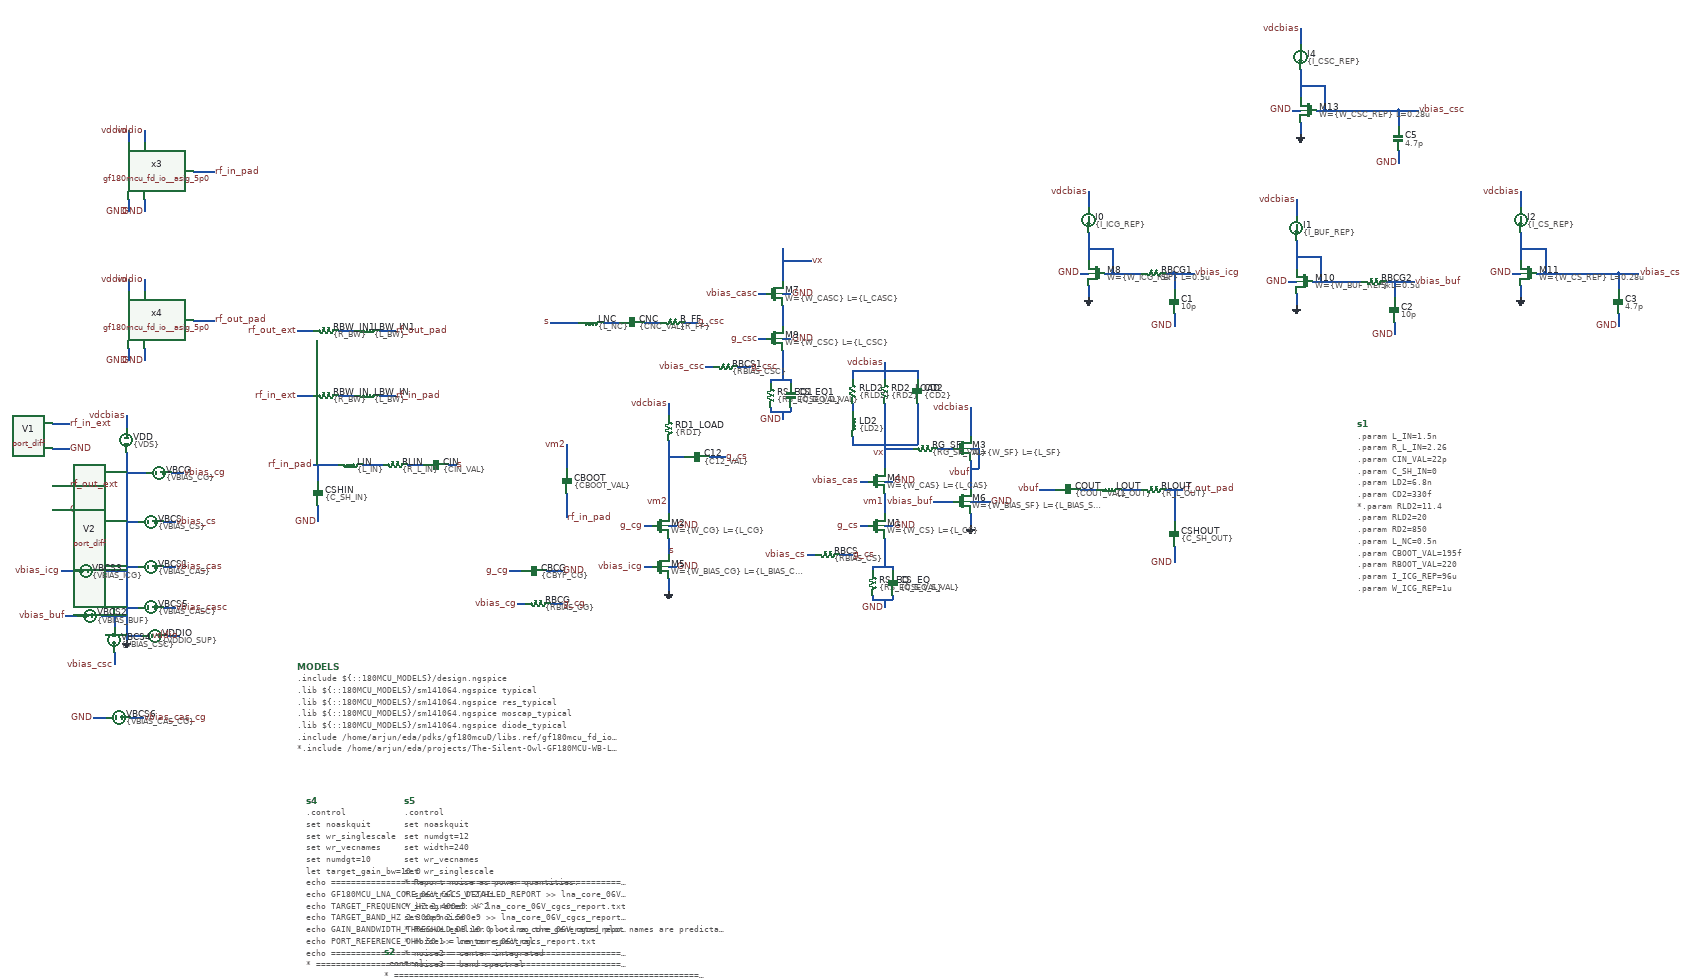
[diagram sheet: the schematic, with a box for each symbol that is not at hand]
v {xschem version=3.4.8RC file_version=1.3}
G {}
K {}
V {}
S {}
F {}
E {}
N -320 -440 -320 -410 {
lab=GND}
N 1010 -260 1030 -260 {
lab=GND}
N -320 -410 -320 -310 {
lab=GND}
N -320 -530 -320 -500 {
lab=vdcbias}
N -320 -390 -270 -390 {
lab=GND}
N -500 -510 -460 -510 {
lab=rf_in_ext}
N -500 -450 -460 -450 {
lab=GND}
N -500 -360 -460 -360 {
lab=rf_out_ext}
N -500 -300 -460 -300 {
lab=GND}
N 1010 -470 1010 -390 {
lab=vm2}
N 1010 -560 1010 -530 {
lab=vdcbias}
N -210 -390 -180 -390 {
lab=vbias_cg}
N 470 -410 490 -410 {
lab=s}
N 140 -410 170 -410 {
lab=rf_in_pad}
N 1010 -430 1050 -430 {
lab=vm2}
N 1110 -430 1150 -430 {
lab=g_cs}
N 1010 -230 1010 -220 {
lab=s}
N 1010 -220 1010 -190 {
lab=s}
N 950 -260 970 -260 {
lab=g_cg}
N -320 -310 -320 -110 {
lab=GND}
N 640 -70 660 -70 {
lab=vbias_cg}
N 720 -70 750 -70 {
lab=g_cg}
N 620 -150 650 -150 {
lab=g_cg}
N 710 -150 750 -150 {
lab=GND}
N 300 -580 340 -580 {
lab=rf_in_pad}
N 200 -580 240 -580 {
lab=#net1}
N 100 -580 140 -580 {
lab=rf_in_ext}
N -320 -270 -290 -270 {
lab=GND}
N -220 10 -190 10 {
lab=vddio}
N 300 -740 340 -740 {
lab=rf_out_pad}
N 200 -740 240 -740 {
lab=#net2}
N 100 -740 140 -740 {
lab=rf_out_ext}
N -320 10 -280 10 {
lab=GND}
N -230 -270 -200 -270 {
lab=vbias_cs
spice_ignore=true}
N 1540 -260 1560 -260 {
lab=GND}
N 1540 -230 1540 -220 {
lab=#net3}
N 1480 -260 1500 -260 {
lab=g_cs}
N 1350 -190 1370 -190 {
lab=vbias_cs}
N 1430 -190 1460 -190 {
lab=g_cs}
N 1540 -220 1540 -160 {
lab=#net3}
N 1540 -660 1540 -620 {
lab=vdcbias}
N 1750 -550 1750 -480 {
lab=vdcbias}
N 1750 -420 1750 -350 {
lab=vbuf}
N 1750 -290 1750 -260 {
lab=GND}
N 1750 -450 1770 -450 {
lab=vbuf}
N 1920 -350 1960 -350 {
lab=vbuf}
N 2020 -350 2060 -350 {
lab=#net4}
N 2120 -350 2170 -350 {
lab=#net5}
N 2230 -350 2270 -350 {
lab=rf_out_pad}
N 2250 -350 2250 -270 {
lab=rf_out_pad}
N 2250 -210 2250 -170 {
lab=GND}
N 150 -410 150 -370 {
lab=rf_in_pad}
N 150 -310 150 -270 {
lab=GND}
N 170 -410 200 -410 {
lab=rf_in_pad}
N 260 -410 310 -410 {
lab=#net6}
N 370 -410 410 -410 {
lab=#net7}
N 1540 -370 1560 -370 {
lab=GND}
N 1540 -340 1540 -330 {
lab=vm1}
N 1480 -370 1500 -370 {
lab=vbias_cas}
N 1540 -560 1540 -480 {
lab=vx}
N 1540 -330 1540 -290 {
lab=vm1}
N -320 -110 -320 20 {
lab=GND}
N -230 -160 -200 -160 {
lab=vbias_cas}
N -320 -160 -290 -160 {
lab=GND}
N 1770 -450 1770 -400 {
lab=vbuf}
N 1750 -400 1770 -400 {
lab=vbuf}
N 1010 -160 1030 -160 {
lab=GND}
N 1010 -130 1010 -120 {
lab=GND}
N 950 -160 970 -160 {
lab=vbias_icg}
N 1010 -120 1010 -100 {
lab=GND}
N 1660 -320 1710 -320 {
lab=vbias_buf}
N 1750 -320 1800 -320 {
lab=GND}
N -470 -40 -440 -40 {
lab=vbias_buf
spice_ignore=true}
N -380 -40 -320 -40 {
lab=GND}
N -480 -150 -450 -150 {
lab=vbias_icg
spice_ignore=true}
N -390 -150 -320 -150 {
lab=GND}
N 1560 -160 1560 -150 {
lab=#net3}
N 1510 -160 1560 -160 {
lab=#net3}
N 1560 -90 1560 -80 {
lab=GND}
N 1510 -80 1560 -80 {
lab=GND}
N 1510 -160 1510 -150 {
lab=#net3}
N 1510 -90 1510 -80 {
lab=GND}
N 1540 -80 1540 -60 {
lab=GND}
N 1670 -450 1710 -450 {
lab=#net8}
N 1540 -450 1610 -450 {
lab=vx}
N -155 -1130 -105 -1130 {
lab=rf_in_pad
}
N -315 -1060 -315 -1030 {
lab=GND
}
N -275 -1060 -275 -1030 {
lab=GND
}
N -315 -1230 -315 -1200 {
lab=vddio
}
N -275 -1230 -275 -1200 {
lab=vddio
}
N -155 -765 -105 -765 {
lab=rf_out_pad
}
N -315 -695 -315 -665 {
lab=GND
}
N -275 -695 -275 -665 {
lab=GND
}
N -315 -865 -315 -835 {
lab=vddio
}
N -275 -865 -275 -835 {
lab=vddio
}
N 1290 -720 1310 -720 {
lab=GND}
N 1290 -690 1290 -680 {
lab=#net9}
N 1230 -720 1250 -720 {
lab=g_csc}
N 1100 -650 1120 -650 {
lab=vbias_csc}
N 1180 -650 1210 -650 {
lab=g_csc}
N 1290 -680 1290 -620 {
lab=#net9}
N 1290 -830 1310 -830 {
lab=GND}
N 1290 -800 1290 -790 {
lab=#net10}
N 1230 -830 1250 -830 {
lab=vbias_casc}
N 1290 -940 1290 -860 {
lab=vx}
N 1290 -790 1290 -750 {
lab=#net10}
N 1310 -620 1310 -610 {
lab=#net9}
N 1260 -620 1310 -620 {
lab=#net9}
N 1310 -550 1310 -540 {
lab=GND}
N 1260 -540 1310 -540 {
lab=GND}
N 1260 -620 1260 -610 {
lab=#net9}
N 1260 -550 1260 -540 {
lab=GND}
N 1290 -540 1290 -520 {
lab=GND}
N 1290 -910 1360 -910 {
lab=vx}
N -230 -270 -200 -270 {lab=vbias_cs
spice_ignore=true}
N -350 -40 -350 -10 {
lab=GND}
N -350 50 -350 80 {
lab=vbias_csc
spice_ignore=true}
N -230 -60 -200 -60 {
lab=vbias_casc}
N -320 -60 -290 -60 {
lab=GND}
N 850 -760 890 -760 {
lab=s}
N 950 -760 990 -760 {
lab=#net11}
N 1010 -330 1010 -320 {
lab=vm2}
N 1010 -320 1010 -290 {lab=vm2}
N -308.75 210 -278.75 210 {
lab=vbias_cas_cg
spice_ignore=true}
N -400 210 -368.75 210 {
lab=GND
spice_ignore=true}
N 1460 -640 1460 -620 {lab=vdcbias}
N 1460 -640 1540 -640 {lab=vdcbias}
N 1460 -560 1460 -540 {lab=#net12}
N 1620 -560 1620 -550 {lab=vx}
N 1540 -460 1620 -460 {lab=vx}
N 1620 -640 1620 -620 {lab=vdcbias}
N 1540 -640 1620 -640 {lab=vdcbias}
N 1620 -550 1620 -540 {lab=vx}
N 1010 -390 1010 -330 {lab=vm2}
N 1540 -480 1540 -400 {lab=vx}
N 1460 -480 1460 -460 {lab=vx}
N 1460 -460 1540 -460 {lab=vx}
N 1620 -540 1620 -460 {lab=vx}
N 720 -760 790 -760 {lab=s}
N 1050 -760 1080 -760 {lab=g_csc}
N 760 -460 760 -400 {lab=vm2}
N 760 -340 760 -280 {lab=rf_in_pad}
N 2020 -880 2040 -880 {
lab=GND}
N 2040 -850 2040 -840 {
lab=GND}
N 2080 -880 2100 -880 {
lab=#net13}
N 2040 -840 2040 -820 {
lab=GND}
N 2040 -980 2040 -910 {lab=#net13}
N 2100 -880 2170 -880 {lab=#net13}
N 2040 -940 2100 -940 {lab=#net13}
N 2100 -940 2100 -880 {lab=#net13}
N 2040 -1080 2040 -1040 {lab=vdcbias}
N 2530 -860 2550 -860 {
lab=GND
}
N 2550 -830 2550 -820 {
lab=GND
}
N 2590 -860 2610 -860 {
lab=#net14
}
N 2550 -820 2550 -800 {
lab=GND
}
N 2550 -960 2550 -890 {lab=#net14
}
N 2550 -920 2610 -920 {lab=#net14
}
N 2610 -920 2610 -860 {lab=#net14
}
N 2550 -1060 2550 -1020 {lab=vdcbias
}
N 2230 -880 2250 -880 {lab=vbias_icg}
N 2250 -880 2250 -840 {lab=vbias_icg}
N 2250 -880 2300 -880 {lab=vbias_icg}
N 2250 -780 2250 -750 {lab=GND}
N 2640 -860 2710 -860 {lab=#net14}
N 2770 -860 2790 -860 {lab=vbias_buf}
N 2790 -860 2790 -820 {lab=vbias_buf}
N 2790 -760 2790 -730 {lab=GND}
N 2610 -860 2640 -860 {lab=#net14}
N 2790 -860 2840 -860 {lab=vbias_buf}
N 3080 -880 3100 -880 {
lab=GND
}
N 3100 -850 3100 -840 {
lab=GND
}
N 3140 -880 3160 -880 {
lab=vbias_cs
}
N 3100 -840 3100 -820 {
lab=GND
}
N 3100 -980 3100 -910 {lab=vbias_cs
}
N 3100 -940 3160 -940 {lab=vbias_cs
}
N 3160 -940 3160 -880 {lab=vbias_cs
}
N 3100 -1080 3100 -1040 {lab=vdcbias
}
N 3190 -880 3260 -880 {lab=vbias_cs}
N 3320 -880 3340 -880 {lab=vbias_cs}
N 3340 -880 3340 -840 {lab=vbias_cs}
N 3340 -780 3340 -750 {lab=GND}
N 3160 -880 3190 -880 {lab=vbias_cs}
N 3340 -880 3390 -880 {lab=vbias_cs}
N 3260 -880 3320 -880 {lab=vbias_cs}
N 2540 -1280 2560 -1280 {
lab=GND
}
N 2560 -1250 2560 -1240 {
lab=GND
}
N 2600 -1280 2620 -1280 {
lab=vbias_csc
}
N 2560 -1240 2560 -1220 {
lab=GND
}
N 2560 -1380 2560 -1310 {lab=vbias_csc
}
N 2560 -1340 2620 -1340 {lab=vbias_csc
}
N 2620 -1340 2620 -1280 {lab=vbias_csc
}
N 2560 -1480 2560 -1440 {lab=vdcbias
}
N 2650 -1280 2720 -1280 {lab=vbias_csc}
N 2780 -1280 2800 -1280 {lab=vbias_csc}
N 2800 -1280 2800 -1240 {lab=vbias_csc}
N 2800 -1180 2800 -1150 {lab=GND}
N 2620 -1280 2650 -1280 {lab=vbias_csc}
N 2800 -1280 2850 -1280 {lab=vbias_csc}
N 2720 -1280 2780 -1280 {lab=vbias_csc}
C {vsource.sym} -240 -390 1 0 {name=VBCG value=\{VBIAS_CG\} savecurrent=false}
C {gnd.sym} 1010 -100 0 0 {name=l1 lab=GND}
C {vsource.sym} -320 -470 0 0 {name=VDD value=\{VDS\} savecurrent=false}
C {capa.sym} 1080 -430 3 0 {name=C12
m=1
value=\{C12_VAL\}
footprint=1206
device="ceramic capacitor"}
C {lab_pin.sym} -460 -510 2 0 {name=p5 sig_type=std_logic lab=rf_in_ext}
C {lab_pin.sym} -460 -450 2 0 {name=p6 sig_type=std_logic lab=GND

}
C {lab_pin.sym} -460 -300 2 0 {name=p8 sig_type=std_logic lab=GND}
C {capa.sym} 440 -410 3 0 {name=CIN
m=1
value=\{CIN_VAL\}
footprint=1206
device="ceramic capacitor"}
C {gnd.sym} -320 20 0 0 {name=l3 lab=GND}
C {lab_pin.sym} -320 -530 0 0 {name=p10 sig_type=std_logic lab=vdcbias
}
C {lab_pin.sym} -180 -390 2 0 {name=p9 sig_type=std_logic lab=vbias_cg}
C {lab_pin.sym} 1010 -560 0 0 {name=p11 sig_type=std_logic lab=vdcbias
}
C {lab_pin.sym} 1150 -430 2 0 {name=p14 sig_type=std_logic lab=g_cs}
C {port_diff.sym} -500 -480 0 0 {name=V1 portnum=1 Z0=50 DCval=0 ACmag=1 ACphase=0 TRANval=""}
C {port_diff.sym} -500 -330 0 0 {name=V2 portnum=2 Z0=50 DCval=0 ACmag=1 ACphase=0 TRANval=""}
C {lab_pin.sym} 1010 -200 2 0 {name=p1 sig_type=std_logic lab=s}
C {lab_pin.sym} 1030 -260 2 0 {name=p2 sig_type=std_logic lab=GND}
C {symbols/nfet_06v0.sym} 990 -260 0 0 {name=M2
L=\{L_CG\}
W=\{W_CG\}
nf=10
m=\{M_CG\}
ad="'int((nf+1)/2) * W/nf * 0.18u'"
pd="'2*int((nf+1)/2) * (W/nf + 0.18u)'"
as="'int((nf+2)/2) * W/nf * 0.18u'"
ps="'2*int((nf+2)/2) * (W/nf + 0.18u)'"
nrd="'0.18u / W'" nrs="'0.18u / W'"
sa=0 sb=0 sd=0
model=nfet_06v0
spiceprefix=X
}
C {lab_pin.sym} 490 -410 2 0 {name=p17 sig_type=std_logic lab=s}
C {res.sym} 690 -70 1 0 {name=RBCG
value=\{RBIAS_CG\}
footprint=1206
device=resistor
m=1}
C {lab_pin.sym} 640 -70 0 0 {name=p20 sig_type=std_logic lab=vbias_cg}
C {lab_pin.sym} 750 -70 2 0 {name=p21 sig_type=std_logic lab=g_cg}
C {capa.sym} 680 -150 3 0 {name=CBCG
m=1
value=\{CBYP_CG\}
footprint=1206
device="ceramic capacitor"}
C {lab_pin.sym} 750 -150 2 0 {name=p19 sig_type=std_logic lab=GND}
C {ind.sym} 270 -580 1 0 {name=LBW_IN
m=1
value=\{L_BW\}
footprint=1206
device=inductor
}
C {res.sym} 170 -580 1 0 {name=RBW_IN
value=\{R_BW\}
footprint=1206
device=resistor
m=1
}
C {lab_pin.sym} 100 -580 0 0 {name=p22 sig_type=std_logic lab=rf_in_ext}
C {lab_pin.sym} 340 -580 2 0 {name=p25 sig_type=std_logic lab=rf_in_pad}
C {vsource.sym} -250 10 1 0 {name=VDDIO value=\{VDDIO_SUP\} savecurrent=false}
C {lab_pin.sym} -190 10 1 0 {name=p27 sig_type=std_logic lab=vddio
}
C {lab_pin.sym} 140 -410 0 0 {name=p13 sig_type=std_logic lab=rf_in_pad}
C {ind.sym} 270 -740 1 0 {name=LBW_IN1
m=1
value=\{L_BW\}
footprint=1206
device=inductor}
C {res.sym} 170 -740 1 0 {name=RBW_IN1
value=\{R_BW\}
footprint=1206
device=resistor
m=1}
C {lab_pin.sym} 100 -740 0 0 {name=p37 sig_type=std_logic lab=rf_out_ext}
C {lab_pin.sym} 340 -740 2 0 {name=p38 sig_type=std_logic lab=rf_out_pad}
C {lab_pin.sym} -460 -360 2 0 {name=p7 sig_type=std_logic lab=rf_out_ext}
C {vsource.sym} -260 -270 1 0 {name=VBCS value=\{VBIAS_CS\} savecurrent=false
spice_ignore=true}
C {lab_pin.sym} -200 -270 2 0 {name=p12 sig_type=std_logic lab=vbias_cs
spice_ignore=true}
C {lab_pin.sym} 950 -260 0 0 {name=p4 sig_type=std_logic lab=g_cg}
C {lab_pin.sym} 620 -150 0 0 {name=p15 sig_type=std_logic lab=g_cg}
C {res.sym} 1010 -500 0 0 {name=RD1_LOAD
value=\{RD1\}
footprint=1206
device=resistor
m=1
}
C {lab_pin.sym} 1540 -60 3 0 {name=p16 sig_type=std_logic lab=GND}
C {lab_pin.sym} 1480 -260 0 0 {name=p18 sig_type=std_logic lab=g_cs}
C {res.sym} 1400 -190 1 0 {name=RBCS
value=\{RBIAS_CS\}
footprint=1206
device=resistor
m=1}
C {lab_pin.sym} 1350 -190 0 0 {name=p23 sig_type=std_logic lab=vbias_cs}
C {lab_pin.sym} 1460 -190 2 0 {name=p24 sig_type=std_logic lab=g_cs}
C {res.sym} 1540 -590 0 0 {name=RD2_LOAD
value=\{RD2\}
footprint=1206
device=resistor
m=1
}
C {lab_pin.sym} 1540 -660 0 0 {name=p39 sig_type=std_logic lab=vdcbias
}
C {symbols/nfet_06v0.sym} 1730 -450 0 0 {name=M3
L=\{L_SF\}
W=\{W_SF\}
nf=10
m=\{M_SF\}
ad="'int((nf+1)/2) * W/nf * 0.18u'"
pd="'2*int((nf+1)/2) * (W/nf + 0.18u)'"
as="'int((nf+2)/2) * W/nf * 0.18u'"
ps="'2*int((nf+2)/2) * (W/nf + 0.18u)'"
nrd="'0.18u / W'" nrs="'0.18u / W'"
sa=0 sb=0 sd=0
model=nfet_06v0
spiceprefix=X
}
C {lab_pin.sym} 1750 -550 0 0 {name=p40 sig_type=std_logic lab=vdcbias
}
C {gnd.sym} 1750 -260 0 0 {name=l2 lab=GND}
C {capa.sym} 1990 -350 3 0 {name=COUT
m=1
value=\{COUT_VAL\}
footprint=1206
device="ceramic capacitor"}
C {lab_pin.sym} 1750 -390 0 0 {name=p43 sig_type=std_logic lab=vbuf}
C {lab_pin.sym} 1920 -350 0 0 {name=p44 sig_type=std_logic lab=vbuf}
C {lab_pin.sym} 2270 -350 2 0 {name=p45 sig_type=std_logic lab=rf_out_pad}
C {ind.sym} 2090 -350 1 0 {name=LOUT
m=1
value=\{L_OUT\}
footprint=1206
device=inductor
}
C {res.sym} 2200 -350 1 0 {name=RLOUT
value=\{R_L_OUT\}
footprint=1206
device=resistor
m=1}
C {capa.sym} 2250 -240 0 0 {name=CSHOUT
m=1
value=\{C_SH_OUT\}
footprint=1206
device="ceramic capacitor"}
C {lab_pin.sym} 2250 -170 3 0 {name=p42 sig_type=std_logic lab=GND}
C {capa.sym} 150 -340 0 0 {name=CSHIN
m=1
value=\{C_SH_IN\}
footprint=1206
device="ceramic capacitor"}
C {lab_pin.sym} 150 -270 3 0 {name=p46 sig_type=std_logic lab=GND}
C {ind.sym} 230 -410 1 0 {name=LIN
m=1
value=\{L_IN\}
footprint=1206
device=inductor
}
C {res.sym} 340 -410 1 0 {name=RLIN
value=\{R_L_IN\}
footprint=1206
device=resistor
m=1
}
C {symbols/nfet_06v0.sym} 1520 -370 0 0 {name=M4
L=\{L_CAS\}
W=\{W_CAS\}
nf=10
m=\{M_CAS\}
ad="'int((nf+1)/2) * W/nf * 0.18u'"
pd="'2*int((nf+1)/2) * (W/nf + 0.18u)'"
as="'int((nf+2)/2) * W/nf * 0.18u'"
ps="'2*int((nf+2)/2) * (W/nf + 0.18u)'"
nrd="'0.18u / W'" nrs="'0.18u / W'"
sa=0 sb=0 sd=0
model=nfet_06v0
spiceprefix=X
}
C {lab_pin.sym} 1480 -370 0 0 {name=p47 sig_type=std_logic lab=vbias_cas}
C {lab_pin.sym} 1560 -370 2 0 {name=p48 sig_type=std_logic lab=GND}
C {vsource.sym} -260 -160 1 0 {name=VBCS1 value=\{VBIAS_CAS\} savecurrent=false}
C {lab_pin.sym} -200 -160 2 0 {name=p49 sig_type=std_logic lab=vbias_cas}
C {lab_pin.sym} 1030 -160 2 0 {name=p41 sig_type=std_logic lab=GND}
C {lab_pin.sym} 950 -160 0 0 {name=p50 sig_type=std_logic lab=vbias_icg}
C {lab_pin.sym} 1660 -320 0 0 {name=p51 sig_type=std_logic lab=vbias_buf}
C {lab_pin.sym} 1800 -320 2 0 {name=p52 sig_type=std_logic lab=GND}
C {vsource.sym} -410 -40 3 0 {name=VBCS2 value=\{VBIAS_BUF\} savecurrent=false
spice_ignore=true}
C {lab_pin.sym} -470 -40 0 0 {name=p53 sig_type=std_logic lab=vbias_buf
spice_ignore=true}
C {vsource.sym} -420 -150 3 0 {name=VBCS3 value=\{VBIAS_ICG\} savecurrent=false
spice_ignore=true}
C {lab_pin.sym} -480 -150 0 0 {name=p54 sig_type=std_logic lab=vbias_icg
spice_ignore=true}
C {symbols/nfet_03v3.sym} 990 -160 0 0 {name=M5
L=\{L_BIAS_CG\}
W=\{W_BIAS_CG\}
nf=10
m=\{M_BIAS_CG\}
ad="'int((nf+1)/2) * W/nf * 0.18u'"
pd="'2*int((nf+1)/2) * (W/nf + 0.18u)'"
as="'int((nf+2)/2) * W/nf * 0.18u'"
ps="'2*int((nf+2)/2) * (W/nf + 0.18u)'"
nrd="'0.18u / W'" nrs="'0.18u / W'"
sa=0 sb=0 sd=0
model=nfet_03v3
spiceprefix=X
}
C {symbols/nfet_03v3.sym} 1730 -320 0 0 {name=M6
L=\{L_BIAS_SF\}
W=\{W_BIAS_SF\}
nf=10
m=\{M_BIAS_SF\}
ad="'int((nf+1)/2) * W/nf * 0.18u'"
pd="'2*int((nf+1)/2) * (W/nf + 0.18u)'"
as="'int((nf+2)/2) * W/nf * 0.18u'"
ps="'2*int((nf+2)/2) * (W/nf + 0.18u)'"
nrd="'0.18u / W'" nrs="'0.18u / W'"
sa=0 sb=0 sd=0
model=nfet_03v3
spiceprefix=X
}
C {res.sym} 1510 -120 0 0 {name=RS_EQ
value=\{RS_EQ_S_VAL\}
footprint=1206
device=resistor
m=1
}
C {capa.sym} 1560 -120 0 0 {name=CS_EQ
m=1
value=\{CSEQ_S_VAL\}
footprint=1206
device="ceramic capacitor"}
C {lab_pin.sym} 1560 -260 2 0 {name=p55 sig_type=std_logic lab=GND}
C {symbols/nfet_03v3.sym} 1520 -260 0 0 {name=M1
L=\{L_CS\}
W=\{W_CS\}
nf=10
m=\{M_CS\}
ad="'int((nf+1)/2) * W/nf * 0.18u'"
pd="'2*int((nf+1)/2) * (W/nf + 0.18u)'"
as="'int((nf+2)/2) * W/nf * 0.18u'"
ps="'2*int((nf+2)/2) * (W/nf + 0.18u)'"
nrd="'0.18u / W'" nrs="'0.18u / W'"
sa=0 sb=0 sd=0
model=nfet_03v3
spiceprefix=X
}
C {res.sym} 1640 -450 1 0 {name=RG_SF
value=\{RG_SF_VAL\}
footprint=1206
device=resistor
m=1}
C {lab_pin.sym} -105 -1130 2 0 {name=p56 sig_type=std_logic lab=rf_in_pad
}
C {lab_pin.sym} -315 -1230 1 0 {name=p57 sig_type=std_logic lab=vddio
}
C {lab_pin.sym} -275 -1230 1 0 {name=p58 sig_type=std_logic lab=vddio
}
C {lab_pin.sym} -315 -1030 3 0 {name=p59 sig_type=std_logic lab=GND
}
C {lab_pin.sym} -275 -1030 3 0 {name=p60 sig_type=std_logic lab=GND
}
C {/home/arjun/eda/projects/The-Silent-Owl-GF180MCU-WB-LNA/analog_pad_sp_paramerters/xschem/gf180mcu_fd_io__asig_5p0.sym} -305 -1130 0 0 {name=x3 model=gf180mcu_fd_io__asig_5p0
}
C {lab_pin.sym} -315 -865 1 0 {name=p61 sig_type=std_logic lab=vddio
}
C {lab_pin.sym} -275 -865 1 0 {name=p62 sig_type=std_logic lab=vddio
}
C {lab_pin.sym} -315 -665 3 0 {name=p63 sig_type=std_logic lab=GND
}
C {lab_pin.sym} -275 -665 3 0 {name=p64 sig_type=std_logic lab=GND
}
C {lab_pin.sym} -105 -765 2 0 {name=p65 sig_type=std_logic lab=rf_out_pad
}
C {/home/arjun/eda/projects/The-Silent-Owl-GF180MCU-WB-LNA/analog_pad_sp_paramerters/xschem/gf180mcu_fd_io__asig_5p0.sym} -305 -765 0 0 {name=x4 model=gf180mcu_fd_io__asig_5p0
}
C {lab_pin.sym} 1290 -520 3 0 {name=p26 sig_type=std_logic lab=GND}
C {lab_pin.sym} 1230 -720 0 0 {name=p28 sig_type=std_logic lab=g_csc}
C {res.sym} 1150 -650 1 0 {name=RBCS1
value=\{RBIAS_CSC\}
footprint=1206
device=resistor
m=1}
C {lab_pin.sym} 1100 -650 0 0 {name=p29 sig_type=std_logic lab=vbias_csc}
C {lab_pin.sym} 1210 -650 2 0 {name=p30 sig_type=std_logic lab=g_csc}
C {symbols/nfet_06v0.sym} 1270 -830 0 0 {name=M7
L=\{L_CASC\}
W=\{W_CASC\}
nf=10
m=\{M_CASC\}
ad="'int((nf+1)/2) * W/nf * 0.18u'"
pd="'2*int((nf+1)/2) * (W/nf + 0.18u)'"
as="'int((nf+2)/2) * W/nf * 0.18u'"
ps="'2*int((nf+2)/2) * (W/nf + 0.18u)'"
nrd="'0.18u / W'" nrs="'0.18u / W'"
sa=0 sb=0 sd=0
model=nfet_06v0
spiceprefix=X
}
C {lab_pin.sym} 1230 -830 0 0 {name=p32 sig_type=std_logic lab=vbias_casc}
C {lab_pin.sym} 1310 -830 2 0 {name=p33 sig_type=std_logic lab=GND}
C {res.sym} 1260 -580 0 0 {name=RS_EQ1
value=\{RS_EQ_D_VAL\}
footprint=1206
device=resistor
m=1
}
C {capa.sym} 1310 -580 0 0 {name=CS_EQ1
m=1
value=\{CSEQ_D_VAL\}
footprint=1206
device="ceramic capacitor"}
C {lab_pin.sym} 1310 -720 2 0 {name=p34 sig_type=std_logic lab=GND}
C {symbols/nfet_03v3.sym} 1270 -720 0 0 {name=M9
L=\{L_CSC\}
W=\{W_CSC\}
nf=4
m=\{M_CSC\}
ad="'int((nf+1)/2) * W/nf * 0.18u'"
pd="'2*int((nf+1)/2) * (W/nf + 0.18u)'"
as="'int((nf+2)/2) * W/nf * 0.18u'"
ps="'2*int((nf+2)/2) * (W/nf + 0.18u)'"
nrd="'0.18u / W'" nrs="'0.18u / W'"
sa=0 sb=0 sd=0
model=nfet_03v3
spiceprefix=X
}
C {vsource.sym} -350 20 2 0 {name=VBCS4 value=\{VBIAS_CSC\} savecurrent=false
spice_ignore=true}
C {lab_pin.sym} -350 80 3 0 {name=p35 sig_type=std_logic lab=vbias_csc
spice_ignore=true}
C {lab_pin.sym} 1540 -440 0 0 {name=p36 sig_type=std_logic lab=vx}
C {lab_pin.sym} 1360 -910 2 0 {name=p66 sig_type=std_logic lab=vx}
C {vsource.sym} -260 -60 1 0 {name=VBCS5 value=\{VBIAS_CASC\} savecurrent=false}
C {lab_pin.sym} -200 -60 2 0 {name=p67 sig_type=std_logic lab=vbias_casc}
C {capa.sym} 920 -760 3 0 {name=CNC
m=1
value=\{CNC_VAL\}
footprint=1206
device="ceramic capacitor"
}
C {lab_pin.sym} 1080 -760 2 0 {name=p68 sig_type=std_logic lab=g_csc}
C {lab_pin.sym} 720 -760 0 0 {name=p69 sig_type=std_logic lab=s}
C {code_shown.sym} 100 85 0 0 {name=MODELS only_toplevel=true
format="tcleval( @value )"
value="
.include $\{::180MCU_MODELS\}/design.ngspice

.lib $\{::180MCU_MODELS\}/sm141064.ngspice typical

.lib $\{::180MCU_MODELS\}/sm141064.ngspice res_typical
.lib $\{::180MCU_MODELS\}/sm141064.ngspice moscap_typical
.lib $\{::180MCU_MODELS\}/sm141064.ngspice diode_typical


.include /home/arjun/eda/pdks/gf180mcuD/libs.ref/gf180mcu_fd_io/spice/gf180mcu_fd_io.spice
*.include /home/arjun/eda/projects/The-Silent-Owl-GF180MCU-WB-LNA/analog_pad_sp_paramerters/spice_files/extracted_gf180mcu_fd_io__asig_5p0.spice
"}
C {code_shown.sym} 2700 -510 0 0 {name=s1 only_toplevel=false value="

.param L_IN=1.5n
.param R_L_IN=2.26

.param CIN_VAL=22p
.param C_SH_IN=0


.param LD2=6.8n
.param CD2=330f
*.param RLD2=11.4
.param RLD2=20
.param RD2=850

.param L_NC=0.5n

.param CBOOT_VAL=195f
.param RBOOT_VAL=220

.param I_ICG_REP=96u
.param W_ICG_REP=1u

.param I_BUF_REP=118u
.param W_BUF_REP=2.5u

.param I_CS_REP=132u
.param W_CS_REP=2u

.param I_CSC_REP=51u
.param W_CSC_REP=2.4u

.param VBIAS_CG=1.9

.param W_CG=40u
.param M_CG=6
.param L_CG=0.60u

.param RD1=850

.param RBIAS_CG=50k
.param CBYP_CG=4.7p

.param CNC_VAL=22p
.param R_FF=470


.param VDS=5.0
.param VDDIO_SUP=5.0

.param L_BW=3n
.param R_BW=0.2

.param RS_EQ_D_VAL=0.25
.param CSEQ_D_VAL=2.2p


.param RS_EQ_S_VAL=0.05
.param CSEQ_S_VAL=100f

.param C12_VAL=6.8p

.param VBIAS_CS=1.20

.param W_CS=20u
.param M_CS=10
.param L_CS=0.28u

.param RBIAS_CS=50k

.param VBIAS_CAS=3.70


.param W_CAS=35u
.param M_CAS=4
.param L_CAS=0.60u




.param W_SF=25u
.param M_SF=10
.param L_SF=0.60u

.param RG_SF_VAL=2

.param COUT_VAL=2.2p

.param L_OUT=1.2n
.param R_L_OUT=1.8

.param C_SH_OUT=220f


.param VBIAS_ICG=1.47

.param L_BIAS_CG=0.50u
.param W_BIAS_CG=15u
.param M_BIAS_CG=1

.param M_BIAS_CG_CM=50


.param VBIAS_BUF=1.30


.param L_BIAS_SF=0.50u
.param W_BIAS_SF=25u
.param M_BIAS_SF=5

.param RBIAS_CSC=50k

.param VBIAS_CSC=0.90

.param L_CSC=0.28u
.param W_CSC=60u
.param M_CSC=4
.param NF_CSC=10


.param VBIAS_CASC=3.20


.param L_CASC=0.60u
.param W_CASC=35u
.param M_CASC=2



"}
C {lab_pin.sym} 1010 -318.75 0 0 {name=p71 sig_type=std_logic lab=vm2}
C {lab_pin.sym} 1540 -318.75 0 0 {name=p72 sig_type=std_logic lab=vm1}
C {vsource.sym} -338.75 210 1 0 {name=VBCS6 value=\{VBIAS_CAS_CG\} savecurrent=false
spice_ignore=true}
C {lab_pin.sym} -278.75 210 2 0 {name=p73 sig_type=std_logic lab=vbias_cas_cg
spice_ignore=true}
C {lab_pin.sym} -400 210 0 0 {name=p74 sig_type=std_logic lab=GND
spice_ignore=true}
C {code.sym} 122.5 413.75 0 0 {name=s4 only_toplevel=false value="

.control

set noaskquit
set wr_singlescale
set wr_vecnames
set numdgt=10

let target_gain_bw=10.0

echo ============================================================ > lna_core_06V_cgcs_report.txt
echo GF180MCU_LNA_CORE_06V_CGCS_DETAILED_REPORT >> lna_core_06V_cgcs_report.txt
echo TARGET_FREQUENCY_HZ 2.400e9 >> lna_core_06V_cgcs_report.txt
echo TARGET_BAND_HZ 2.300e9 2.500e9 >> lna_core_06V_cgcs_report.txt
echo GAIN_BANDWIDTH_THRESHOLD_DB 10.0 >> lna_core_06V_cgcs_report.txt
echo PORT_REFERENCE_OHM 50 >> lna_core_06V_cgcs_report.txt
echo ============================================================ >> lna_core_06V_cgcs_report.txt

* =============================================================================
* DC OPERATING POINT
* =============================================================================

op

let pdcop=1e3*(abs(i(VDD))*v(vdcbias)+abs(i(VDDIO))*v(vddio))
let icoreop=abs(i(VDD))
let iioop=abs(i(VDDIO))

let vsop=v(s)
let vdop=v(vm2)
let vnet3op=v(net3)
let vnet8op=v(net8)
let vbufop=v(vbuf)
let vgcsop=v(g_cs)
let vgcgop=v(g_cg)

let id1op=abs(@m.xm1.m0[id])
let gm1op=@m.xm1.m0[gm]
let gmb1op=@m.xm1.m0[gmbs]
let gds1op=@m.xm1.m0[gds]
let vgs1op=@m.xm1.m0[vgs]
let vds1op=@m.xm1.m0[vds]
let vbs1op=@m.xm1.m0[vbs]
let vth1op=@m.xm1.m0[vth]
let vov1op=vgs1op-vth1op
let vdsat1op=abs(@m.xm1.m0[vdsat])
let sat1op=vds1op-vdsat1op
let gmid1op=gm1op/(id1op+1e-30)
let ro1op=1/(gds1op+1e-30)

let id2op=abs(@m.xm2.m0[id])
let gm2op=@m.xm2.m0[gm]
let gmb2op=@m.xm2.m0[gmbs]
let gds2op=@m.xm2.m0[gds]
let vgs2op=@m.xm2.m0[vgs]
let vds2op=@m.xm2.m0[vds]
let vbs2op=@m.xm2.m0[vbs]
let vth2op=@m.xm2.m0[vth]
let vov2op=vgs2op-vth2op
let vdsat2op=abs(@m.xm2.m0[vdsat])
let sat2op=vds2op-vdsat2op
let gmid2op=gm2op/(id2op+1e-30)
let ro2op=1/(gds2op+1e-30)

let id3op=abs(@m.xm3.m0[id])
let gm3op=@m.xm3.m0[gm]
let gmb3op=@m.xm3.m0[gmbs]
let gds3op=@m.xm3.m0[gds]
let vgs3op=@m.xm3.m0[vgs]
let vds3op=@m.xm3.m0[vds]
let vbs3op=@m.xm3.m0[vbs]
let vth3op=@m.xm3.m0[vth]
let vov3op=vgs3op-vth3op
let vdsat3op=abs(@m.xm3.m0[vdsat])
let sat3op=vds3op-vdsat3op
let gmid3op=gm3op/(id3op+1e-30)
let ro3op=1/(gds3op+1e-30)

let id4op=abs(@m.xm4.m0[id])
let gm4op=@m.xm4.m0[gm]
let gmb4op=@m.xm4.m0[gmbs]
let gds4op=@m.xm4.m0[gds]
let vgs4op=@m.xm4.m0[vgs]
let vds4op=@m.xm4.m0[vds]
let vbs4op=@m.xm4.m0[vbs]
let vth4op=@m.xm4.m0[vth]
let vov4op=vgs4op-vth4op
let vdsat4op=abs(@m.xm4.m0[vdsat])
let sat4op=vds4op-vdsat4op
let gmid4op=gm4op/(id4op+1e-30)
let ro4op=1/(gds4op+1e-30)

let id5op=abs(@m.xm5.m0[id])
let gm5op=@m.xm5.m0[gm]
let gmb5op=@m.xm5.m0[gmbs]
let gds5op=@m.xm5.m0[gds]
let vgs5op=@m.xm5.m0[vgs]
let vds5op=@m.xm5.m0[vds]
let vbs5op=@m.xm5.m0[vbs]
let vth5op=@m.xm5.m0[vth]
let vov5op=vgs5op-vth5op
let vdsat5op=abs(@m.xm5.m0[vdsat])
let sat5op=vds5op-vdsat5op
let gmid5op=gm5op/(id5op+1e-30)
let ro5op=1/(gds5op+1e-30)

let id6op=abs(@m.xm6.m0[id])
let gm6op=@m.xm6.m0[gm]
let gmb6op=@m.xm6.m0[gmbs]
let gds6op=@m.xm6.m0[gds]
let vgs6op=@m.xm6.m0[vgs]
let vds6op=@m.xm6.m0[vds]
let vbs6op=@m.xm6.m0[vbs]
let vth6op=@m.xm6.m0[vth]
let vov6op=vgs6op-vth6op
let vdsat6op=abs(@m.xm6.m0[vdsat])
let sat6op=vds6op-vdsat6op
let gmid6op=gm6op/(id6op+1e-30)
let ro6op=1/(gds6op+1e-30)

let id7op=abs(@m.xm7.m0[id])
let gm7op=@m.xm7.m0[gm]
let gmb7op=@m.xm7.m0[gmbs]
let gds7op=@m.xm7.m0[gds]
let vgs7op=@m.xm7.m0[vgs]
let vds7op=@m.xm7.m0[vds]
let vbs7op=@m.xm7.m0[vbs]
let vth7op=@m.xm7.m0[vth]
let vov7op=vgs7op-vth7op
let vdsat7op=abs(@m.xm7.m0[vdsat])
let sat7op=vds7op-vdsat7op
let gmid7op=gm7op/(id7op+1e-30)
let ro7op=1/(gds7op+1e-30)

let id9op=abs(@m.xm9.m0[id])
let gm9op=@m.xm9.m0[gm]
let gmb9op=@m.xm9.m0[gmbs]
let gds9op=@m.xm9.m0[gds]
let vgs9op=@m.xm9.m0[vgs]
let vds9op=@m.xm9.m0[vds]
let vbs9op=@m.xm9.m0[vbs]
let vth9op=@m.xm9.m0[vth]
let vov9op=vgs9op-vth9op
let vdsat9op=abs(@m.xm9.m0[vdsat])
let sat9op=vds9op-vdsat9op
let gmid9op=gm9op/(id9op+1e-30)
let ro9op=1/(gds9op+1e-30)

let vnet9op=vnet3op+vds1op
let vnet9check=vnet8op-vds4op
let vnet9diff=vnet9op-vnet9check
let vnet10op=vsop+vds2op
let vnet10check=vdop-vds7op
let vnet10diff=vnet10op-vnet10check

set op_pdc=$&pdcop
set op_icore=$&icoreop
set op_iio=$&iioop
set op_vs=$&vsop
set op_vnet10=$&vnet10op
set op_vnet10check=$&vnet10check
set op_vnet10diff=$&vnet10diff
set op_vd=$&vdop
set op_vnet3=$&vnet3op
set op_vnet9=$&vnet9op
set op_vnet9check=$&vnet9check
set op_vnet9diff=$&vnet9diff
set op_vnet8=$&vnet8op
set op_vbuf=$&vbufop
set op_vgcs=$&vgcsop
set op_vgcg=$&vgcgop

set op_id1=$&id1op
set op_gm1=$&gm1op
set op_gmb1=$&gmb1op
set op_gds1=$&gds1op
set op_vgs1=$&vgs1op
set op_vds1=$&vds1op
set op_vbs1=$&vbs1op
set op_vth1=$&vth1op
set op_vov1=$&vov1op
set op_vdsat1=$&vdsat1op
set op_sat1=$&sat1op
set op_gmid1=$&gmid1op
set op_ro1=$&ro1op

set op_id2=$&id2op
set op_gm2=$&gm2op
set op_gmb2=$&gmb2op
set op_gds2=$&gds2op
set op_vgs2=$&vgs2op
set op_vds2=$&vds2op
set op_vbs2=$&vbs2op
set op_vth2=$&vth2op
set op_vov2=$&vov2op
set op_vdsat2=$&vdsat2op
set op_sat2=$&sat2op
set op_gmid2=$&gmid2op
set op_ro2=$&ro2op

set op_id3=$&id3op
set op_gm3=$&gm3op
set op_gmb3=$&gmb3op
set op_gds3=$&gds3op
set op_vgs3=$&vgs3op
set op_vds3=$&vds3op
set op_vbs3=$&vbs3op
set op_vth3=$&vth3op
set op_vov3=$&vov3op
set op_vdsat3=$&vdsat3op
set op_sat3=$&sat3op
set op_gmid3=$&gmid3op
set op_ro3=$&ro3op

set op_id4=$&id4op
set op_gm4=$&gm4op
set op_gmb4=$&gmb4op
set op_gds4=$&gds4op
set op_vgs4=$&vgs4op
set op_vds4=$&vds4op
set op_vbs4=$&vbs4op
set op_vth4=$&vth4op
set op_vov4=$&vov4op
set op_vdsat4=$&vdsat4op
set op_sat4=$&sat4op
set op_gmid4=$&gmid4op
set op_ro4=$&ro4op

set op_id5=$&id5op
set op_gm5=$&gm5op
set op_gmb5=$&gmb5op
set op_gds5=$&gds5op
set op_vgs5=$&vgs5op
set op_vds5=$&vds5op
set op_vbs5=$&vbs5op
set op_vth5=$&vth5op
set op_vov5=$&vov5op
set op_vdsat5=$&vdsat5op
set op_sat5=$&sat5op
set op_gmid5=$&gmid5op
set op_ro5=$&ro5op

set op_id6=$&id6op
set op_gm6=$&gm6op
set op_gmb6=$&gmb6op
set op_gds6=$&gds6op
set op_vgs6=$&vgs6op
set op_vds6=$&vds6op
set op_vbs6=$&vbs6op
set op_vth6=$&vth6op
set op_vov6=$&vov6op
set op_vdsat6=$&vdsat6op
set op_sat6=$&sat6op
set op_gmid6=$&gmid6op
set op_ro6=$&ro6op

set op_id7=$&id7op
set op_gm7=$&gm7op
set op_gmb7=$&gmb7op
set op_gds7=$&gds7op
set op_vgs7=$&vgs7op
set op_vds7=$&vds7op
set op_vbs7=$&vbs7op
set op_vth7=$&vth7op
set op_vov7=$&vov7op
set op_vdsat7=$&vdsat7op
set op_sat7=$&sat7op
set op_gmid7=$&gmid7op
set op_ro7=$&ro7op

set op_id9=$&id9op
set op_gm9=$&gm9op
set op_gmb9=$&gmb9op
set op_gds9=$&gds9op
set op_vgs9=$&vgs9op
set op_vds9=$&vds9op
set op_vbs9=$&vbs9op
set op_vth9=$&vth9op
set op_vov9=$&vov9op
set op_vdsat9=$&vdsat9op
set op_sat9=$&sat9op
set op_gmid9=$&gmid9op
set op_ro9=$&ro9op

echo ============================================================ >> lna_core_06V_cgcs_report.txt
echo DC_SUPPLY_AND_NODE_VOLTAGES >> lna_core_06V_cgcs_report.txt
echo PDC_mW $op_pdc ICORE_A $op_icore IIO_A $op_iio >> lna_core_06V_cgcs_report.txt
echo NODES_V S $op_vs NET10_DERIVED $op_vnet10 VM2 $op_vd NET3 $op_vnet3 NET9_DERIVED $op_vnet9 NET8 $op_vnet8 VBUF $op_vbuf G_CS $op_vgcs G_CG $op_vgcg >> lna_core_06V_cgcs_report.txt
echo HIDDEN_NODE_CHECKS NET10_FROM_XM2 $op_vnet10 NET10_FROM_XM7 $op_vnet10check DIFFERENCE $op_vnet10diff NET9_FROM_XM1 $op_vnet9 NET9_FROM_XM4 $op_vnet9check DIFFERENCE $op_vnet9diff >> lna_core_06V_cgcs_report.txt
echo ============================================================ >> lna_core_06V_cgcs_report.txt
echo TRANSISTOR_OPERATING_POINTS >> lna_core_06V_cgcs_report.txt
echo FIELDS ID_A GM_S GMBS_S GDS_S VGS_V VDS_V VBS_V VTH_V VOV_V VDSAT_V SAT_MARGIN_V GM_OVER_ID_1_PER_V RO_OHM >> lna_core_06V_cgcs_report.txt
echo XM1_CS ID $op_id1 GM $op_gm1 GMBS $op_gmb1 GDS $op_gds1 VGS $op_vgs1 VDS $op_vds1 VBS $op_vbs1 VTH $op_vth1 VOV $op_vov1 VDSAT $op_vdsat1 SAT_MARGIN $op_sat1 GMID $op_gmid1 RO $op_ro1 >> lna_core_06V_cgcs_report.txt
echo XM2_CG ID $op_id2 GM $op_gm2 GMBS $op_gmb2 GDS $op_gds2 VGS $op_vgs2 VDS $op_vds2 VBS $op_vbs2 VTH $op_vth2 VOV $op_vov2 VDSAT $op_vdsat2 SAT_MARGIN $op_sat2 GMID $op_gmid2 RO $op_ro2 >> lna_core_06V_cgcs_report.txt
echo XM3_SOURCE_FOLLOWER ID $op_id3 GM $op_gm3 GMBS $op_gmb3 GDS $op_gds3 VGS $op_vgs3 VDS $op_vds3 VBS $op_vbs3 VTH $op_vth3 VOV $op_vov3 VDSAT $op_vdsat3 SAT_MARGIN $op_sat3 GMID $op_gmid3 RO $op_ro3 >> lna_core_06V_cgcs_report.txt
echo XM4_CS_CASCODE ID $op_id4 GM $op_gm4 GMBS $op_gmb4 GDS $op_gds4 VGS $op_vgs4 VDS $op_vds4 VBS $op_vbs4 VTH $op_vth4 VOV $op_vov4 VDSAT $op_vdsat4 SAT_MARGIN $op_sat4 GMID $op_gmid4 RO $op_ro4 >> lna_core_06V_cgcs_report.txt
echo XM5_CG_CURRENT_SINK ID $op_id5 GM $op_gm5 GMBS $op_gmb5 GDS $op_gds5 VGS $op_vgs5 VDS $op_vds5 VBS $op_vbs5 VTH $op_vth5 VOV $op_vov5 VDSAT $op_vdsat5 SAT_MARGIN $op_sat5 GMID $op_gmid5 RO $op_ro5 >> lna_core_06V_cgcs_report.txt
echo XM6_BUFFER_CURRENT_SINK ID $op_id6 GM $op_gm6 GMBS $op_gmb6 GDS $op_gds6 VGS $op_vgs6 VDS $op_vds6 VBS $op_vbs6 VTH $op_vth6 VOV $op_vov6 VDSAT $op_vdsat6 SAT_MARGIN $op_sat6 GMID $op_gmid6 RO $op_ro6 >> lna_core_06V_cgcs_report.txt
echo XM7_CG_CASCODE ID $op_id7 GM $op_gm7 GMBS $op_gmb7 GDS $op_gds7 VGS $op_vgs7 VDS $op_vds7 VBS $op_vbs7 VTH $op_vth7 VOV $op_vov7 VDSAT $op_vdsat7 SAT_MARGIN $op_sat7 GMID $op_gmid7 RO $op_ro7 >> lna_core_06V_cgcs_report.txt
echo XM9_CANCELLATION_CS ID $op_id9 GM $op_gm9 GMBS $op_gmb9 GDS $op_gds9 VGS $op_vgs9 VDS $op_vds9 VBS $op_vbs9 VTH $op_vth9 VOV $op_vov9 VDSAT $op_vdsat9 SAT_MARGIN $op_sat9 GMID $op_gmid9 RO $op_ro9 >> lna_core_06V_cgcs_report.txt

destroy $curplot

* =============================================================================
* SINGLE BROADBAND RF ANALYSIS
* One reset and one SP run are used for all 1 MHz to 7 GHz RF results.
* Target-band values are extracted from the same dataset.
* This avoids inconsistent port excitation state between repeated SP runs.
* 7000 points from 1 MHz to 7 GHz gives exactly 1 MHz spacing.
* =============================================================================

reset
sp lin 7000 1Meg 7Gig 1
set rfplot=$curplot

let fghz=frequency/1e9

let s11db=db(s_1_1)
let s21db=db(s_2_1)
let s12db=db(s_1_2)
let s22db=db(s_2_2)

let s11re=real(s_1_1)
let s11im=imag(s_1_1)
let s21re=real(s_2_1)
let s21im=imag(s_2_1)
let s12re=real(s_1_2)
let s12im=imag(s_1_2)
let s22re=real(s_2_2)
let s22im=imag(s_2_2)

let nfdb=real(NF)
let nfmin_db=real(NFmin)

let delta=s_1_1*s_2_2-s_1_2*s_2_1
let delta_mag=mag(delta)
let a11=mag(s_1_1)
let a12=mag(s_1_2)
let a21=mag(s_2_1)
let a22=mag(s_2_2)
let mu=(1-a11*a11)/(mag(s_2_2-delta*conj(s_1_1))+mag(s_1_2*s_2_1))
let mup=(1-a22*a22)/(mag(s_1_1-delta*conj(s_2_2))+mag(s_1_2*s_2_1))
let kval=(1-a11*a11-a22*a22+delta_mag*delta_mag)/(2*a12*a21)

let zin=50*(1+s_1_1)/(1-s_1_1)
let zout=50*(1+s_2_2)/(1-s_2_2)
let zin_re=real(zin)
let zin_im=imag(zin)
let zout_re=real(zout)
let zout_im=imag(zout)

let npts=length(frequency)

* Find indices nearest 2.300 GHz, 2.400 GHz and 2.500 GHz.
let ilo=0
let icenter=0
let ihi=0
let errlo=abs(frequency[0]-2.3e9)
let errcenter=abs(frequency[0]-2.4e9)
let errhi=abs(frequency[0]-2.5e9)
let ii=1
while ii < npts
let newerr=abs(frequency[ii]-2.3e9)
if newerr < errlo
let errlo=newerr
let ilo=ii
end
let newerr=abs(frequency[ii]-2.4e9)
if newerr < errcenter
let errcenter=newerr
let icenter=ii
end
let newerr=abs(frequency[ii]-2.5e9)
if newerr < errhi
let errhi=newerr
let ihi=ii
end
let ii=ii+1
end

* Values at the sample nearest 2.400 GHz.
let center_freq=frequency[icenter]
let s11c=s11db[icenter]
let s21c=s21db[icenter]
let s12c=s12db[icenter]
let s22c=s22db[icenter]
let s11rc=s11re[icenter]
let s11ic=s11im[icenter]
let s21rc=s21re[icenter]
let s21ic=s21im[icenter]
let s12rc=s12re[icenter]
let s12ic=s12im[icenter]
let s22rc=s22re[icenter]
let s22ic=s22im[icenter]
let nfc=nfdb[icenter]
let nfminc=nfmin_db[icenter]
let muc=mu[icenter]
let mupc=mup[icenter]
let kc=kval[icenter]
let dmc=delta_mag[icenter]
let zinrc=zin_re[icenter]
let zinic=zin_im[icenter]
let zoutrc=zout_re[icenter]
let zoutic=zout_im[icenter]

* Initialize target-band extrema.
let s11min=s11db[ilo]
let s11max=s11db[ilo]
let s21min=s21db[ilo]
let s21max=s21db[ilo]
let s12min=s12db[ilo]
let s12max=s12db[ilo]
let s22min=s22db[ilo]
let s22max=s22db[ilo]
let nfbandmin=nfdb[ilo]
let nfbandmax=nfdb[ilo]
let nfminbandmin=nfmin_db[ilo]
let nfminbandmax=nfmin_db[ilo]
let mumin=mu[ilo]
let mupmin=mup[ilo]
let kmin=kval[ilo]
let dmax=delta_mag[ilo]

let s11min_i=ilo
let s11max_i=ilo
let s21min_i=ilo
let s21max_i=ilo
let s12min_i=ilo
let s12max_i=ilo
let s22min_i=ilo
let s22max_i=ilo
let nfmin_i=ilo
let nfmax_i=ilo
let nfminpar_min_i=ilo
let nfminpar_max_i=ilo
let mumin_i=ilo
let mupmin_i=ilo
let kmin_i=ilo
let dmax_i=ilo

* Scan 2.300 GHz to 2.500 GHz.
let ii=ilo
while ii <= ihi
if s11db[ii] < s11min
let s11min=s11db[ii]
let s11min_i=ii
end
if s11db[ii] > s11max
let s11max=s11db[ii]
let s11max_i=ii
end
if s21db[ii] < s21min
let s21min=s21db[ii]
let s21min_i=ii
end
if s21db[ii] > s21max
let s21max=s21db[ii]
let s21max_i=ii
end
if s12db[ii] < s12min
let s12min=s12db[ii]
let s12min_i=ii
end
if s12db[ii] > s12max
let s12max=s12db[ii]
let s12max_i=ii
end
if s22db[ii] < s22min
let s22min=s22db[ii]
let s22min_i=ii
end
if s22db[ii] > s22max
let s22max=s22db[ii]
let s22max_i=ii
end
if nfdb[ii] < nfbandmin
let nfbandmin=nfdb[ii]
let nfmin_i=ii
end
if nfdb[ii] > nfbandmax
let nfbandmax=nfdb[ii]
let nfmax_i=ii
end
if nfmin_db[ii] < nfminbandmin
let nfminbandmin=nfmin_db[ii]
let nfminpar_min_i=ii
end
if nfmin_db[ii] > nfminbandmax
let nfminbandmax=nfmin_db[ii]
let nfminpar_max_i=ii
end
if mu[ii] < mumin
let mumin=mu[ii]
let mumin_i=ii
end
if mup[ii] < mupmin
let mupmin=mup[ii]
let mupmin_i=ii
end
if kval[ii] < kmin
let kmin=kval[ii]
let kmin_i=ii
end
if delta_mag[ii] > dmax
let dmax=delta_mag[ii]
let dmax_i=ii
end
let ii=ii+1
end

let gain_ripple=s21max-s21min

let s11min_f=frequency[s11min_i]
let s11max_f=frequency[s11max_i]
let s21min_f=frequency[s21min_i]
let s21max_f=frequency[s21max_i]
let s12min_f=frequency[s12min_i]
let s12max_f=frequency[s12max_i]
let s22min_f=frequency[s22min_i]
let s22max_f=frequency[s22max_i]
let nfmin_f=frequency[nfmin_i]
let nfmax_f=frequency[nfmax_i]
let nfminpar_min_f=frequency[nfminpar_min_i]
let nfminpar_max_f=frequency[nfminpar_max_i]
let mumin_f=frequency[mumin_i]
let mupmin_f=frequency[mupmin_i]
let kmin_f=frequency[kmin_i]
let dmax_f=frequency[dmax_i]

* Find the broadband S21 peak and its index.
let imax=0
let gainmax=s21db[0]
let ii=1
while ii < npts
if s21db[ii] > gainmax
let gainmax=s21db[ii]
let imax=ii
end
let ii=ii+1
end
let peakfreq=frequency[imax]

echo ============================================================ >> lna_core_06V_cgcs_report.txt
echo RF_AT_2P400_GHZ_FROM_SINGLE_BROADBAND_SWEEP >> lna_core_06V_cgcs_report.txt
echo ACTUAL_SAMPLE_HZ $&center_freq >> lna_core_06V_cgcs_report.txt
echo S11_DB $&s11c REAL $&s11rc IMAG $&s11ic >> lna_core_06V_cgcs_report.txt
echo S21_DB $&s21c REAL $&s21rc IMAG $&s21ic >> lna_core_06V_cgcs_report.txt
echo S12_DB $&s12c REAL $&s12rc IMAG $&s12ic >> lna_core_06V_cgcs_report.txt
echo S22_DB $&s22c REAL $&s22rc IMAG $&s22ic >> lna_core_06V_cgcs_report.txt
echo NF_DB $&nfc NFMIN_DB $&nfminc >> lna_core_06V_cgcs_report.txt
echo MU $&muc MUP $&mupc K $&kc DELTA_MAG $&dmc >> lna_core_06V_cgcs_report.txt
echo ZIN_OHM RE $&zinrc IM $&zinic >> lna_core_06V_cgcs_report.txt
echo ZOUT_OHM RE $&zoutrc IM $&zoutic >> lna_core_06V_cgcs_report.txt

echo ============================================================ >> lna_core_06V_cgcs_report.txt
echo RF_MIN_MAX_FROM_2P300_TO_2P500_GHZ >> lna_core_06V_cgcs_report.txt
echo S11_MIN_DB $&s11min AT_HZ $&s11min_f S11_MAX_DB $&s11max AT_HZ $&s11max_f >> lna_core_06V_cgcs_report.txt
echo S21_MIN_DB $&s21min AT_HZ $&s21min_f S21_MAX_DB $&s21max AT_HZ $&s21max_f GAIN_RIPPLE_DB $&gain_ripple >> lna_core_06V_cgcs_report.txt
echo S12_MIN_DB $&s12min AT_HZ $&s12min_f S12_MAX_DB $&s12max AT_HZ $&s12max_f >> lna_core_06V_cgcs_report.txt
echo S22_MIN_DB $&s22min AT_HZ $&s22min_f S22_MAX_DB $&s22max AT_HZ $&s22max_f >> lna_core_06V_cgcs_report.txt
echo NF_MIN_DB $&nfbandmin AT_HZ $&nfmin_f NF_MAX_DB $&nfbandmax AT_HZ $&nfmax_f >> lna_core_06V_cgcs_report.txt
echo NFMIN_PARAMETER_MIN_DB $&nfminbandmin AT_HZ $&nfminpar_min_f NFMIN_PARAMETER_MAX_DB $&nfminbandmax AT_HZ $&nfminpar_max_f >> lna_core_06V_cgcs_report.txt
echo MU_MIN $&mumin AT_HZ $&mumin_f MUP_MIN $&mupmin AT_HZ $&mupmin_f >> lna_core_06V_cgcs_report.txt
echo K_MIN $&kmin AT_HZ $&kmin_f DELTA_MAX $&dmax AT_HZ $&dmax_f >> lna_core_06V_cgcs_report.txt

echo ============================================================ >> lna_core_06V_cgcs_report.txt
echo BROADBAND_GAIN_CHECK_1MHZ_TO_7GHZ >> lna_core_06V_cgcs_report.txt
echo GAIN_AT_2P4_DB $&s21c >> lna_core_06V_cgcs_report.txt
echo BROADBAND_PEAK_HZ $&peakfreq PEAK_GAIN_DB $&gainmax >> lna_core_06V_cgcs_report.txt

echo ============================================================ >> lna_core_06V_cgcs_report.txt
echo TARGET_CENTERED_S21_GE_10DB_BAND >> lna_core_06V_cgcs_report.txt
if s21c >= 10.0
let bwlo=icenter
let bwhi=icenter
let search=1
while search = 1
if bwlo > 0
if s21db[bwlo-1] >= 10.0
let bwlo=bwlo-1
else
let search=0
end
else
let search=0
end
end
let search=1
while search = 1
if bwhi < npts-1
if s21db[bwhi+1] >= 10.0
let bwhi=bwhi+1
else
let search=0
end
else
let search=0
end
end
let bwflo=frequency[bwlo]
let bwfhi=frequency[bwhi]
let bwval=bwfhi-bwflo
let bwcenter=0.5*(bwfhi+bwflo)
let bwfbw=100*bwval/(bwcenter+1e-30)
echo LOWER_HZ $&bwflo UPPER_HZ $&bwfhi BANDWIDTH_HZ $&bwval BAND_CENTER_HZ $&bwcenter FRACTIONAL_BW_PERCENT $&bwfbw >> lna_core_06V_cgcs_report.txt
else
echo NO_VALID_TARGET_CENTERED_BAND S21_AT_2P4_DB $&s21c >> lna_core_06V_cgcs_report.txt
end

echo ============================================================ >> lna_core_06V_cgcs_report.txt
echo GLOBAL_CONTIGUOUS_S21_GE_10DB_BAND_AROUND_PEAK >> lna_core_06V_cgcs_report.txt
if gainmax >= 10.0
let bwlo=imax
let bwhi=imax
let search=1
while search = 1
if bwlo > 0
if s21db[bwlo-1] >= 10.0
let bwlo=bwlo-1
else
let search=0
end
else
let search=0
end
end
let search=1
while search = 1
if bwhi < npts-1
if s21db[bwhi+1] >= 10.0
let bwhi=bwhi+1
else
let search=0
end
else
let search=0
end
end
let bwflo=frequency[bwlo]
let bwfhi=frequency[bwhi]
let bwval=bwfhi-bwflo
let bwcenter=0.5*(bwfhi+bwflo)
let bwfbw=100*bwval/(bwcenter+1e-30)
echo LOWER_HZ $&bwflo UPPER_HZ $&bwfhi BANDWIDTH_HZ $&bwval BAND_CENTER_HZ $&bwcenter FRACTIONAL_BW_PERCENT $&bwfbw >> lna_core_06V_cgcs_report.txt
else
echo NO_S21_ABOVE_10DB_FROM_1MHZ_TO_7GHZ PEAK_GAIN_DB $&gainmax PEAK_FREQUENCY_HZ $&peakfreq >> lna_core_06V_cgcs_report.txt
end

wrdata lna_core_06V_cgcs_target_band.dat frequency s_1_1 s_2_1 s_1_2 s_2_2 s11db s21db s12db s22db nfdb nfmin_db kval mu mup delta_mag zin_re zin_im zout_re zout_im
wrdata lna_core_06V_cgcs_broadband.dat frequency s11db s21db s12db s22db nfdb nfmin_db kval mu mup delta_mag zin_re zin_im zout_re zout_im

* =============================================================================
* NOISE-CANCELLATION A/B PROOF
*
* ON baseline:
*   CNC = optimized value (8.2 pF).
*
* OFF baseline:
*   CNC is opened to 1e-18 F using alterparam.
*   XM7/XM9 remain biased and connected to vx, so their DC current,
*   output loading and intrinsic noise remain present. Only the sensed
*   RF path from node s to g_csc is removed. This is a conservative
*   demonstration of whether the sensing/cancellation action reduces NF.
*
* Positive NF_IMPROVEMENT_DB = NF_OFF - NF_ON means cancellation helps.
* =============================================================================

* Preserve the cancellation-ON plot generated above.
set nc_on_plot=$rfplot

* Open only the noise-sensing capacitor.
alterparam CNC_VAL = 1e-18
reset

sp lin 7000 1Meg 7Gig 1
set nc_off_plot=$curplot

let fghz_nc=frequency/1e9

* Copy ON data into this plot so ON and OFF vectors share one scale.
let nf_nc_on=\{$nc_on_plot\}.nfdb
let s21_nc_on=\{$nc_on_plot\}.s21db
let s11_nc_on=\{$nc_on_plot\}.s11db
let s22_nc_on=\{$nc_on_plot\}.s22db

* OFF data with the cancellation sensing path opened.
let nf_nc_off=real(NF)
let s21_nc_off=db(s_2_1)
let s11_nc_off=db(s_1_1)
let s22_nc_off=db(s_2_2)

* Main proof vector. Positive values mean lower NF with cancellation ON.
let nf_improvement_db=nf_nc_off-nf_nc_on
let gain_change_on_minus_off_db=s21_nc_on-s21_nc_off

let nc_npts=length(frequency)

* Locate 2.3, 2.4 and 2.5 GHz in the OFF dataset.
let nc_ilo=0
let nc_icenter=0
let nc_ihi=0
let nc_errlo=abs(frequency[0]-2.3e9)
let nc_errcenter=abs(frequency[0]-2.4e9)
let nc_errhi=abs(frequency[0]-2.5e9)
let nc_ii=1
while nc_ii < nc_npts
  let nc_newerr=abs(frequency[nc_ii]-2.3e9)
  if nc_newerr < nc_errlo
    let nc_errlo=nc_newerr
    let nc_ilo=nc_ii
  end

  let nc_newerr=abs(frequency[nc_ii]-2.4e9)
  if nc_newerr < nc_errcenter
    let nc_errcenter=nc_newerr
    let nc_icenter=nc_ii
  end

  let nc_newerr=abs(frequency[nc_ii]-2.5e9)
  if nc_newerr < nc_errhi
    let nc_errhi=nc_newerr
    let nc_ihi=nc_ii
  end

  let nc_ii=nc_ii+1
end

* Center-frequency results.
let nc_freq_center=frequency[nc_icenter]
let nc_nf_on_c=nf_nc_on[nc_icenter]
let nc_nf_off_c=nf_nc_off[nc_icenter]
let nc_imp_c=nf_improvement_db[nc_icenter]

let nc_s21_on_c=s21_nc_on[nc_icenter]
let nc_s21_off_c=s21_nc_off[nc_icenter]
let nc_gain_delta_c=gain_change_on_minus_off_db[nc_icenter]

let nc_s11_on_c=s11_nc_on[nc_icenter]
let nc_s11_off_c=s11_nc_off[nc_icenter]
let nc_s22_on_c=s22_nc_on[nc_icenter]
let nc_s22_off_c=s22_nc_off[nc_icenter]

* Improvement extrema over 2.3-2.5 GHz.
let nc_imp_min=nf_improvement_db[nc_ilo]
let nc_imp_max=nf_improvement_db[nc_ilo]
let nc_imp_min_i=nc_ilo
let nc_imp_max_i=nc_ilo

let nc_ii=nc_ilo
while nc_ii <= nc_ihi
  if nf_improvement_db[nc_ii] < nc_imp_min
    let nc_imp_min=nf_improvement_db[nc_ii]
    let nc_imp_min_i=nc_ii
  end
  if nf_improvement_db[nc_ii] > nc_imp_max
    let nc_imp_max=nf_improvement_db[nc_ii]
    let nc_imp_max_i=nc_ii
  end
  let nc_ii=nc_ii+1
end

let nc_imp_min_f=frequency[nc_imp_min_i]
let nc_imp_max_f=frequency[nc_imp_max_i]

* User-selectable threshold for a practically meaningful center improvement.
let nc_practical_threshold_db=0.20

echo ============================================================ >> lna_core_06V_cgcs_report.txt
echo NOISE_CANCELLATION_AB_PROOF >> lna_core_06V_cgcs_report.txt
echo METHOD ON_CNC_8P2PF OFF_CNC_1E_MINUS18F_XM7_XM9_STILL_BIASED_AND_LOADING_RETAINED >> lna_core_06V_cgcs_report.txt
echo ACTUAL_CENTER_SAMPLE_HZ $&nc_freq_center >> lna_core_06V_cgcs_report.txt
echo NF_ON_DB $&nc_nf_on_c NF_OFF_DB $&nc_nf_off_c NF_IMPROVEMENT_DB $&nc_imp_c >> lna_core_06V_cgcs_report.txt
echo S21_ON_DB $&nc_s21_on_c S21_OFF_DB $&nc_s21_off_c S21_ON_MINUS_OFF_DB $&nc_gain_delta_c >> lna_core_06V_cgcs_report.txt
echo S11_ON_DB $&nc_s11_on_c S11_OFF_DB $&nc_s11_off_c >> lna_core_06V_cgcs_report.txt
echo S22_ON_DB $&nc_s22_on_c S22_OFF_DB $&nc_s22_off_c >> lna_core_06V_cgcs_report.txt
echo NF_IMPROVEMENT_MIN_DB_2P3_TO_2P5 $&nc_imp_min AT_HZ $&nc_imp_min_f >> lna_core_06V_cgcs_report.txt
echo NF_IMPROVEMENT_MAX_DB_2P3_TO_2P5 $&nc_imp_max AT_HZ $&nc_imp_max_f >> lna_core_06V_cgcs_report.txt
echo PRACTICAL_CENTER_THRESHOLD_DB $&nc_practical_threshold_db >> lna_core_06V_cgcs_report.txt

if nc_imp_c > 0
  echo CENTER_DIRECTIONAL_TEST PASS_CANCELLATION_LOWERS_NF >> lna_core_06V_cgcs_report.txt
else
  echo CENTER_DIRECTIONAL_TEST FAIL_CANCELLATION_DOES_NOT_LOWER_NF >> lna_core_06V_cgcs_report.txt
end

if nc_imp_min > 0
  echo FULL_TARGET_BAND_TEST PASS_CANCELLATION_LOWERS_NF_ACROSS_2P3_TO_2P5_GHZ >> lna_core_06V_cgcs_report.txt
else
  echo FULL_TARGET_BAND_TEST FAIL_NF_IMPROVEMENT_NOT_POSITIVE_ACROSS_ENTIRE_TARGET_BAND >> lna_core_06V_cgcs_report.txt
end

if nc_imp_c >= nc_practical_threshold_db
  echo PRACTICAL_CENTER_TEST PASS_IMPROVEMENT_AT_LEAST_0P20_DB >> lna_core_06V_cgcs_report.txt
else
  echo PRACTICAL_CENTER_TEST FAIL_IMPROVEMENT_BELOW_0P20_DB >> lna_core_06V_cgcs_report.txt
end

wrdata lna_core_06V_cgcs_noise_cancellation.dat nf_nc_on nf_nc_off nf_improvement_db s21_nc_on s21_nc_off s11_nc_on s11_nc_off s22_nc_on s22_nc_off

* Restore the optimized cancellation capacitor before subsequent analyses.
alterparam CNC_VAL = 22p
reset

* =============================================================================
* WIDEBAND STABILITY 10 MHZ TO 30 GHZ
* =============================================================================

sp dec 101 10Meg 30G 1
set stabilityplot=$curplot

let wbdelta=s_1_1*s_2_2-s_1_2*s_2_1
let wbmd=mag(wbdelta)
let wba11=mag(s_1_1)
let wba12=mag(s_1_2)
let wba21=mag(s_2_1)
let wba22=mag(s_2_2)
let wbmu=(1-wba11*wba11)/(mag(s_2_2-wbdelta*conj(s_1_1))+mag(s_1_2*s_2_1))
let wbmup=(1-wba22*wba22)/(mag(s_1_1-wbdelta*conj(s_2_2))+mag(s_1_2*s_2_1))
let wbk=(1-wba11*wba11-wba22*wba22+wbmd*wbmd)/(2*wba12*wba21)

let wbkmin=minimum(wbk)
let wbmumin=minimum(wbmu)
let wbmupmin=minimum(wbmup)
let wbdmax=maximum(wbmd)

set final_wbkmin=$&wbkmin
set final_wbmumin=$&wbmumin
set final_wbmupmin=$&wbmupmin
set final_wbdmax=$&wbdmax

echo ============================================================ >> lna_core_06V_cgcs_report.txt
echo WIDEBAND_STABILITY_10MHZ_TO_30GHZ >> lna_core_06V_cgcs_report.txt
echo K_MIN $final_wbkmin MU_MIN $final_wbmumin MUP_MIN $final_wbmupmin DELTA_MAX $final_wbdmax >> lna_core_06V_cgcs_report.txt

wrdata lna_core_06V_cgcs_stability.dat frequency wbk wbmu wbmup wbmd

let wbfghz=frequency/1e9

echo ============================================================ >> lna_core_06V_cgcs_report.txt
echo OUTPUT_FILES >> lna_core_06V_cgcs_report.txt
echo REPORT lna_core_06V_cgcs_report.txt >> lna_core_06V_cgcs_report.txt
echo TARGET_DATA lna_core_06V_cgcs_target_band.dat >> lna_core_06V_cgcs_report.txt
echo BROADBAND_DATA lna_core_06V_cgcs_broadband.dat >> lna_core_06V_cgcs_report.txt
echo STABILITY_DATA lna_core_06V_cgcs_stability.dat >> lna_core_06V_cgcs_report.txt
echo NOISE_CANCELLATION_DATA lna_core_06V_cgcs_noise_cancellation.dat >> lna_core_06V_cgcs_report.txt
echo PLOTS S_PARAMETERS NF_NFMIN NOISE_CANCELLATION_ON_OFF NF_IMPROVEMENT S21_ON_OFF >> lna_core_06V_cgcs_report.txt
echo ============================================================ >> lna_core_06V_cgcs_report.txt



* =============================================================================
* VISIBLE PLOTS
* Plot commands are intentionally placed at the very end.
* Neither rfplot nor stabilityplot is destroyed or reset afterward.
* =============================================================================

setplot $rfplot
setscale fghz

* Target band 2.3 GHz to 2.5 GHz
plot s11db xlimit 2.3 2.5
plot s21db xlimit 2.3 2.5
plot s12db xlimit 2.3 2.5
plot s22db xlimit 2.3 2.5
plot nfdb nfmin_db xlimit 2.3 2.5
* plot mu mup xlimit 2.3 2.5
* plot kval xlimit 2.3 2.5
* plot delta_mag xlimit 2.3 2.5
* plot zin_re zin_im xlimit 2.3 2.5
* plot zout_re zout_im xlimit 2.3 2.5

* Broadband 1 MHz to 7 GHz
plot s11db xlimit 0 7
plot s21db xlimit 0 7
plot s12db xlimit 0 7
plot s22db xlimit 0 7
plot nfdb nfmin_db xlimit 0 7
* plot mu mup xlimit 0 7
* plot kval xlimit 0 7
* plot delta_mag xlimit 0 7
* plot zin_re zin_im xlimit 0 7
* plot zout_re zout_im xlimit 0 7

* Noise-cancellation proof plots
setplot $nc_off_plot
setscale fghz_nc
set xbrushwidth=2

* Plot 1: direct NF comparison; ON must lie below OFF.
plot nf_nc_on nf_nc_off xlimit 2.3 2.5 xlabel 'Frequency (GHz)' ylabel 'Noise figure (dB)'

* Plot 2: positive improvement proves cancellation benefit.
plot nf_improvement_db xlimit 2.3 2.5 xlabel 'Frequency (GHz)' ylabel 'NF OFF - NF ON (dB)'

* Plot 3: signal-gain sanity check for the same A/B experiment.
plot s21_nc_on s21_nc_off xlimit 2.3 2.5 xlabel 'Frequency (GHz)' ylabel 'S21 (dB)'

* Wideband stability 10 MHz to 30 GHz
* setplot $stabilityplot
* setscale wbfghz
* plot wbmu wbmup
* plot wbk
* plot wbmd

.endc

"
}
C {ind.sym} 1460 -510 0 0 {name=LD2
m=1
value=\{LD2\}
footprint=1206
device=inductor
}
C {capa.sym} 1620 -590 0 0 {name=CD2
m=1
value=\{CD2\}
footprint=1206
device="ceramic capacitor"}
C {res.sym} 1460 -590 0 0 {name=RLD2
value=\{RLD2\}
footprint=1206
device=resistor
m=1
}
C {code.sym} 362.5 413.75 0 0 {name=s5 only_toplevel=false value="

.control

set noaskquit
set numdgt=12
set width=240
set wr_vecnames
set wr_singlescale

* Report noise as power quantities:
* spectral:   V^2/Hz
* integrated: V^2
set sqrnoise

* Remove earlier plots so the generated plot names are predictable:
* noise1 = center spectral
* noise2 = center integrated
* noise3 = band spectral
* noise4 = band integrated
destroy all

echo ============================================================
echo BEGIN_PER_SOURCE_NOISE_REPORT
echo CIRCUIT GF180MCU_LNA_CORE_06V_CGCS
echo OUTPUT_NODE rf_out_ext
echo INPUT_SOURCE V1
echo SPECTRAL_UNITS V2_PER_HZ
echo INTEGRATED_UNITS V2
echo ============================================================

* =============================================================================
* 1. CENTER-FREQUENCY BREAKDOWN
*
* Three frequency points:
*   2.399 GHz
*   2.400 GHz
*   2.401 GHz
*
* pts_per_summary = 1 prints every internal noise generator at every point.
* =============================================================================

reset

echo ============================================================
echo CENTER_NOISE_BREAKDOWN_BEGIN
echo FREQUENCIES_HZ 2.399E9 2.400E9 2.401E9
echo ============================================================

noise v(rf_out_ext) V1 lin 3 2.399G 2.401G 1

* Save total output/input PSD versus frequency.
setplot noise1
wrdata lna_noise_center_total_psd.dat onoise_spectrum inoise_spectrum
write lna_noise_center_spectral.raw all

* Save and print integrated center-window noise.
setplot noise2
print onoise_total inoise_total
write lna_noise_center_integrated.raw all

echo ============================================================
echo CENTER_NOISE_BREAKDOWN_END
echo ============================================================

* =============================================================================
* 2. TARGET-BAND BREAKDOWN, 2.3–2.5 GHz
*
* 201 points produce 1 MHz spacing.
*
* pts_per_summary = 20 prints detailed per-source contributions
* approximately every 20 MHz:
*   2.300, 2.320, ..., 2.500 GHz
*
* Change 20 to 1 to print every source at every 1 MHz point.
* =============================================================================

reset

echo ============================================================
echo TARGET_BAND_NOISE_BREAKDOWN_BEGIN
echo START_HZ 2.300E9
echo STOP_HZ 2.500E9
echo POINTS 201
echo DEVICE_SUMMARY_EVERY_POINTS 20
echo ============================================================

noise v(rf_out_ext) V1 lin 201 2.3G 2.5G 20

* Save total spectral noise.
setplot noise3
wrdata lna_noise_band_total_psd.dat onoise_spectrum inoise_spectrum
write lna_noise_band_spectral.raw all

* Save and print integrated target-band noise.
setplot noise4
print onoise_total inoise_total
write lna_noise_band_integrated.raw all

echo ============================================================
echo TARGET_BAND_NOISE_BREAKDOWN_END
echo ============================================================

echo IDEAL_CAPACITORS_AND_INDUCTORS_HAVE_ZERO_INTRINSIC_NOISE
echo INDUCTOR_LOSS_APPEARS_UNDER_ITS_EXPLICIT_SERIES_RESISTOR
echo PAD_NOISE_APPEARS_USING_HIERARCHICAL_X3_AND_X4_INTERNAL_NAMES

echo ============================================================
echo GENERATED_DATA_FILES
echo CENTER_TOTAL_PSD lna_noise_center_total_psd.dat
echo CENTER_SPECTRAL_RAW lna_noise_center_spectral.raw
echo CENTER_INTEGRATED_RAW lna_noise_center_integrated.raw
echo BAND_TOTAL_PSD lna_noise_band_total_psd.dat
echo BAND_SPECTRAL_RAW lna_noise_band_spectral.raw
echo BAND_INTEGRATED_RAW lna_noise_band_integrated.raw
echo END_PER_SOURCE_NOISE_REPORT
echo ============================================================

unset sqrnoise

* =============================================================================
* COMPLETE NOISE-CONTRIBUTION EXTRACTION
* =============================================================================

set numdgt=12
set width=240
set wr_vecnames
set wr_singlescale
set sqrnoise
set filetype=ascii

* Makes noise plot numbering predictable:
* noise1/noise2 = center contributor analysis
* noise3/noise4 = band contributor analysis
* noise5/noise6 = full-resolution total band analysis
destroy all

* =============================================================================
* 1. CONTRIBUTOR BREAKDOWN AROUND 2.4 GHz
* =============================================================================

reset
noise v(rf_out_ext) V1 lin 3 2.399G 2.401G 1

setplot noise1

* List every vector ngspice generated.
display > lna_noise_center_vector_names.txt

* ASCII raw-format text file containing every available contributor vector.
write lna_noise_center_all_sources.txt

* Simple table containing only total noise.
wrdata lna_noise_center_total_psd.dat onoise_spectrum inoise_spectrum

setplot noise2
write lna_noise_center_integrated_all.txt
print onoise_total inoise_total > lna_noise_center_integrated_totals.txt

* =============================================================================
* 2. CONTRIBUTOR BREAKDOWN ACROSS 2.3–2.5 GHz
*
* Eleven points:
* 2.300, 2.320, ..., 2.500 GHz
*
* Final argument 1 requests contributor data at every simulated point.
* =============================================================================

reset
noise v(rf_out_ext) V1 lin 11 2.3G 2.5G 1

setplot noise3

display > lna_noise_band_vector_names.txt
write lna_noise_band_all_sources.txt
wrdata lna_noise_band_summary_total_psd.dat onoise_spectrum inoise_spectrum

setplot noise4
write lna_noise_band_integrated_all.txt
print onoise_total inoise_total > lna_noise_band_integrated_totals.txt

* =============================================================================
* 3. FULL-RESOLUTION TOTAL NOISE
*
* No pts_per_summary argument is used here.
* This preserves all 201 frequency points at 1 MHz spacing.
* =============================================================================

reset
noise v(rf_out_ext) V1 lin 201 2.3G 2.5G

setplot noise5

wrdata lna_noise_band_full_resolution_total_psd.dat onoise_spectrum inoise_spectrum
write lna_noise_band_full_resolution_raw.txt

setplot noise6
print onoise_total inoise_total > lna_noise_band_full_resolution_integrated.txt

unset sqrnoise

.endc

"
spice_ignore=true}
C {ind.sym} 820 -760 3 1 {name=LNC
m=1
value=\{L_NC\}
footprint=1206
device=inductor
spice_ignore=short}
C {code.sym} 312.5 783.75 0 0 {name=s2 only_toplevel=false value="

.control

* =============================================================================
* EXECUTION SETTINGS
* =============================================================================

set noaskquit
set wr_singlescale
set wr_vecnames
set numdgt=10

set num_threads=6
option klu

* =============================================================================
* COMPACT FULL JOINT S11 OPTIMIZATION
*
* Number of candidates:
*
*   3^9 = 19683
*
* Swept parameters:
*
*   I_ICG_REP
*   M_CG
*   VBIAS_CG
*   L_IN
*   CIN_VAL
*   C_SH_IN
*   CNC_VAL
*   R_FF
*   CBYP_CG
*
* Fixed parameters:
*
*   W_ICG_REP = 0.25 um
*   W_CG       = 40 um
*   L_CG       = 0.60 um
*
* Physical restrictions:
*
*   L_IN      <= 1.5 nH
*   CIN_VAL   <= 22 pF
*   CNC_VAL   <= 22 pF
*   CBYP_CG   <= 22 pF
*
* Search simulation:
*
*   41 points from 2.3 GHz to 2.5 GHz
*   Frequency spacing = 5 MHz
*   Vector index 20   = exactly 2.4 GHz
*
* Optimization objective:
*
*   Minimize maximum(S11_dB) over 2.3-2.5 GHz.
*
* Since S11 is negative, maximum(S11_dB) is the least-negative
* and therefore worst return loss in the target band.
*
* Validity constraints:
*
*   S21 minimum over band >= 19.0 dB
*   NF maximum over band   <= 4.5 dB
*   PDC                    <= 150 mW
*   XM2 saturation margin  >= 100 mV
*   XM5 saturation margin  >= 100 mV
*   0.40 V <= source node  <= 1.50 V
*   0.30 mA <= ID_XM2      <= 3.50 mA
*
* Exactly two output files:
*
*   compact_full_sweep_detailed.txt
*   compact_full_sweep_summary.txt
* =============================================================================

* =============================================================================
* FIXED DEVICE GEOMETRIES
* =============================================================================

alterparam W_ICG_REP = 0.25u
alterparam W_CG      = 40u
alterparam L_CG      = 0.60u

reset

* =============================================================================
* DETAILED-FILE HEADER
* =============================================================================

echo ============================================================ > compact_full_sweep_detailed.txt
echo GF180MCU_COMPACT_LNA_FULL_JOINT_S11_SWEEP >> compact_full_sweep_detailed.txt
echo REQUESTED_SOLVER KLU >> compact_full_sweep_detailed.txt
echo REQUESTED_THREADS 6 >> compact_full_sweep_detailed.txt
echo TOTAL_CANDIDATES 19683 >> compact_full_sweep_detailed.txt
echo TARGET_BAND_HZ 2.300E9 2.500E9 >> compact_full_sweep_detailed.txt
echo SEARCH_POINTS 41 >> compact_full_sweep_detailed.txt
echo CENTER_FREQUENCY_HZ 2.400E9 >> compact_full_sweep_detailed.txt
echo OBJECTIVE MINIMIZE_WORST_CASE_S11_DB >> compact_full_sweep_detailed.txt
echo CONSTRAINT_S21_MIN_DB 19.0 >> compact_full_sweep_detailed.txt
echo CONSTRAINT_NF_MAX_DB 4.5 >> compact_full_sweep_detailed.txt
echo CONSTRAINT_PDC_MAX_W 0.150 >> compact_full_sweep_detailed.txt
echo CONSTRAINT_XM2_SAT_MARGIN_MIN_V 0.100 >> compact_full_sweep_detailed.txt
echo CONSTRAINT_XM5_SAT_MARGIN_MIN_V 0.100 >> compact_full_sweep_detailed.txt
echo FIXED_W_ICG_REP_M 0.25E-6 >> compact_full_sweep_detailed.txt
echo FIXED_W_CG_M 40E-6 >> compact_full_sweep_detailed.txt
echo FIXED_L_CG_M 0.60E-6 >> compact_full_sweep_detailed.txt
echo ============================================================ >> compact_full_sweep_detailed.txt

echo IREP_A MCG VBIAS_CG_V L_IN_H CIN_F CSH_F CNC_F RFF_OHM CBYP_F VBIAS_ICG_V VS_V ID2_A GM2_S GMB2_S SAT2_V SAT5_V PDC_W S11_CENTER_DB S11_WORST_DB S11_BEST_DB S21_CENTER_DB S21_MIN_DB S21_MAX_DB S12_CENTER_DB S22_CENTER_DB NF_CENTER_DB NF_MAX_DB NFMIN_CENTER_DB ZIN_RE_OHM ZIN_IM_OHM GAMMA_MAG REFLECTED_POWER_PERCENT VSWR VALID >> compact_full_sweep_detailed.txt

* =============================================================================
* GLOBAL BEST-CANDIDATE STORAGE
* =============================================================================

set best_found=0
set best_score=1000

* Default values are the previously verified compact solution.
set best_irep=20u
set best_mcg=6
set best_vcg=2.05

set best_lin=1.5n
set best_cin=22p
set best_csh=0

set best_cnc=22p
set best_rff=220
set best_cbyp=4.7p

set best_vbi=0
set best_vs=0
set best_id2=0
set best_gm2=0
set best_gmb2=0

set best_sat2=0
set best_sat5=0
set best_pdc=0

set best_s11c=0
set best_s11worst=0
set best_s11best=0

set best_s21c=0
set best_s21min=0
set best_s21max=0

set best_s12c=0
set best_s22c=0

set best_nfc=0
set best_nfmax=0
set best_nfminc=0

set best_zinre=0
set best_zinim=0

set best_gamma=0
set best_reflpct=0
set best_vswr=0

* =============================================================================
* FULL NINE-DIMENSION CARTESIAN SWEEP
*
* Ranges are centered on the compact result and extended beyond every
* boundary previously selected by the optimizer.
*
* I_ICG_REP:
*   16, 20, 24 uA
*
* M_CG:
*   5, 6, 7
*
* VBIAS_CG:
*   1.90, 2.05, 2.20 V
*
* L_IN:
*   1.25, 1.40, 1.50 nH
*
* CIN_VAL:
*   15, 18, 22 pF
*
* C_SH_IN:
*   0, 50, 100 fF
*
* CNC_VAL:
*   15, 18, 22 pF
*
* R_FF:
*   220, 470, 1000 ohm
*
* CBYP_CG:
*   1.0, 2.2, 4.7 pF
* =============================================================================

foreach irep 16u 20u 24u

  foreach mcg 5 6 7

    foreach vcg 1.90 2.05 2.20

      foreach linval 1.25n 1.40n 1.50n

        foreach cinval 15p 18p 22p

          foreach cshval 0 50f 100f

            foreach cncval 15p 18p 22p

              foreach rffval 220 470 1000

                foreach cbypval 1.0p 2.2p 4.7p

                  * ===========================================================
                  * APPLY THIS CANDIDATE
                  * ===========================================================

                  alterparam W_ICG_REP = 0.25u
                  alterparam W_CG      = 40u
                  alterparam L_CG      = 0.60u

                  alterparam I_ICG_REP = $irep
                  alterparam M_CG      = $mcg
                  alterparam VBIAS_CG  = $vcg

                  alterparam L_IN      = $linval
                  alterparam CIN_VAL   = $cinval
                  alterparam C_SH_IN   = $cshval

                  alterparam CNC_VAL   = $cncval
                  alterparam R_FF      = $rffval
                  alterparam CBYP_CG   = $cbypval

                  reset

                  * ===========================================================
                  * DC OPERATING-POINT ANALYSIS
                  * ===========================================================

                  op

                  let dc_vbi  = v(vbias_icg)
                  let dc_vs   = v(s)

                  let dc_id2  = abs(@m.xm2.m0[id])
                  let dc_gm2  = @m.xm2.m0[gm]
                  let dc_gmb2 = @m.xm2.m0[gmbs]

                  let dc_vds2   = abs(@m.xm2.m0[vds])
                  let dc_vdsat2 = abs(@m.xm2.m0[vdsat])
                  let dc_sat2   = dc_vds2-dc_vdsat2

                  let dc_vds5   = abs(@m.xm5.m0[vds])
                  let dc_vdsat5 = abs(@m.xm5.m0[vdsat])
                  let dc_sat5   = dc_vds5-dc_vdsat5

                  let dc_pdc = abs(v(vdcbias)*i(VDD))

                  * Copy OP vectors into persistent control variables before
                  * destroying the OP plot.

                  set cur_vbi=$&dc_vbi
                  set cur_vs=$&dc_vs

                  set cur_id2=$&dc_id2
                  set cur_gm2=$&dc_gm2
                  set cur_gmb2=$&dc_gmb2

                  set cur_sat2=$&dc_sat2
                  set cur_sat5=$&dc_sat5
                  set cur_pdc=$&dc_pdc

                  destroy $curplot

                  * ===========================================================
                  * TARGET-BAND S-PARAMETER AND NOISE ANALYSIS
                  *
                  * A reset is deliberately performed immediately before SP.
                  * ===========================================================

                  reset
                  sp lin 41 2.3G 2.5G 1

                  let s11db = db(s_1_1)
                  let s21db = db(s_2_1)
                  let s12db = db(s_1_2)
                  let s22db = db(s_2_2)

                  let nfdb    = real(NF)
                  let nfmindb = real(NFmin)

                  let zin    = 50*(1+s_1_1)/(1-s_1_1)
                  let zin_re = real(zin)
                  let zin_im = imag(zin)

                  * Center-frequency values at index 20 = 2.4 GHz.

                  let s11c = s11db[20]
                  let s21c = s21db[20]
                  let s12c = s12db[20]
                  let s22c = s22db[20]

                  let nfc    = nfdb[20]
                  let nfminc = nfmindb[20]

                  let zinrec = zin_re[20]
                  let zinimc = zin_im[20]

                  * Target-band extrema.

                  let s11worst = maximum(s11db)
                  let s11best  = minimum(s11db)

                  let s21min = minimum(s21db)
                  let s21max = maximum(s21db)

                  let nfmax = maximum(nfdb)

                  * Center-frequency reflection quantities.

                  let gammac  = mag(s_1_1[20])
                  let reflpct = 100*gammac*gammac
                  let vswrc   = (1+gammac)/(1-gammac)

                  * ===========================================================
                  * VALIDITY CHECK
                  * ===========================================================

                  let valid=0

                  if $cur_vbi >= 0.80
                    if $cur_vbi <= 3.00

                      if $cur_vs >= 0.40
                        if $cur_vs <= 1.50

                          if $cur_id2 >= 0.00030
                            if $cur_id2 <= 0.00350

                              if $cur_sat2 >= 0.100
                                if $cur_sat5 >= 0.100

                                  if $cur_pdc <= 0.150

                                    if s21min >= 19.0

                                      if nfmax <= 4.5
                                        let valid=1
                                      end

                                    end
                                  end
                                end
                              end
                            end
                          end
                        end
                      end
                    end
                  end

                  * ===========================================================
                  * WRITE THIS CANDIDATE TO THE SINGLE DETAILED FILE
                  * ===========================================================

                  echo $irep $mcg $vcg $linval $cinval $cshval $cncval $rffval $cbypval $cur_vbi $cur_vs $cur_id2 $cur_gm2 $cur_gmb2 $cur_sat2 $cur_sat5 $cur_pdc $&s11c $&s11worst $&s11best $&s21c $&s21min $&s21max $&s12c $&s22c $&nfc $&nfmax $&nfminc $&zinrec $&zinimc $&gammac $&reflpct $&vswrc $&valid >> compact_full_sweep_detailed.txt

                  * ===========================================================
                  * UPDATE GLOBAL BEST VALID CANDIDATE
                  * ===========================================================

                  if valid = 1

                    let old_score=$best_score

                    if s11worst < old_score

                      set best_found=1
                      set best_score=$&s11worst

                      set best_irep=$irep
                      set best_mcg=$mcg
                      set best_vcg=$vcg

                      set best_lin=$linval
                      set best_cin=$cinval
                      set best_csh=$cshval

                      set best_cnc=$cncval
                      set best_rff=$rffval
                      set best_cbyp=$cbypval

                      set best_vbi=$cur_vbi
                      set best_vs=$cur_vs

                      set best_id2=$cur_id2
                      set best_gm2=$cur_gm2
                      set best_gmb2=$cur_gmb2

                      set best_sat2=$cur_sat2
                      set best_sat5=$cur_sat5
                      set best_pdc=$cur_pdc

                      set best_s11c=$&s11c
                      set best_s11worst=$&s11worst
                      set best_s11best=$&s11best

                      set best_s21c=$&s21c
                      set best_s21min=$&s21min
                      set best_s21max=$&s21max

                      set best_s12c=$&s12c
                      set best_s22c=$&s22c

                      set best_nfc=$&nfc
                      set best_nfmax=$&nfmax
                      set best_nfminc=$&nfminc

                      set best_zinre=$&zinrec
                      set best_zinim=$&zinimc

                      set best_gamma=$&gammac
                      set best_reflpct=$&reflpct
                      set best_vswr=$&vswrc

                    end
                  end

                  destroy $curplot

                end
              end
            end
          end
        end
      end
    end
  end
end

* =============================================================================
* APPEND SEARCH-WINNER INFORMATION TO DETAILED FILE
* =============================================================================

echo ============================================================ >> compact_full_sweep_detailed.txt
echo FULL_SWEEP_COMPLETE >> compact_full_sweep_detailed.txt
echo VALID_BEST_FOUND $best_found >> compact_full_sweep_detailed.txt
echo BEST_SEARCH_WORST_S11_DB $best_score >> compact_full_sweep_detailed.txt
echo ============================================================ >> compact_full_sweep_detailed.txt

* =============================================================================
* FINAL HIGH-RESOLUTION VERIFICATION
* =============================================================================

if $best_found = 1

  * ---------------------------------------------------------------------------
  * Apply the best candidate.
  * ---------------------------------------------------------------------------

  alterparam W_ICG_REP = 0.25u
  alterparam W_CG      = 40u
  alterparam L_CG      = 0.60u

  alterparam I_ICG_REP = $best_irep
  alterparam M_CG      = $best_mcg
  alterparam VBIAS_CG  = $best_vcg

  alterparam L_IN      = $best_lin
  alterparam CIN_VAL   = $best_cin
  alterparam C_SH_IN   = $best_csh

  alterparam CNC_VAL   = $best_cnc
  alterparam R_FF      = $best_rff
  alterparam CBYP_CG   = $best_cbyp

  reset

  * ---------------------------------------------------------------------------
  * Final DC operating point.
  * ---------------------------------------------------------------------------

  op

  let final_vbi  = v(vbias_icg)
  let final_vs   = v(s)

  let final_id2  = abs(@m.xm2.m0[id])
  let final_gm2  = @m.xm2.m0[gm]
  let final_gmb2 = @m.xm2.m0[gmbs]

  let final_vds2   = abs(@m.xm2.m0[vds])
  let final_vdsat2 = abs(@m.xm2.m0[vdsat])
  let final_sat2   = final_vds2-final_vdsat2

  let final_vds5   = abs(@m.xm5.m0[vds])
  let final_vdsat5 = abs(@m.xm5.m0[vdsat])
  let final_sat5   = final_vds5-final_vdsat5

  let final_pdc = abs(v(vdcbias)*i(VDD))

  set final_vbi_c=$&final_vbi
  set final_vs_c=$&final_vs

  set final_id2_c=$&final_id2
  set final_gm2_c=$&final_gm2
  set final_gmb2_c=$&final_gmb2

  set final_sat2_c=$&final_sat2
  set final_sat5_c=$&final_sat5
  set final_pdc_c=$&final_pdc

  destroy $curplot

  * ---------------------------------------------------------------------------
  * Final 401-point target-band verification.
  *
  * 2.3 GHz to 2.5 GHz:
  *   401 points
  *   0.5 MHz spacing
  *   index 200 = exactly 2.4 GHz
  * ---------------------------------------------------------------------------

  reset
  sp lin 401 2.3G 2.5G 1

  let s11db = db(s_1_1)
  let s21db = db(s_2_1)
  let s12db = db(s_1_2)
  let s22db = db(s_2_2)

  let nfdb    = real(NF)
  let nfmindb = real(NFmin)

  let zin    = 50*(1+s_1_1)/(1-s_1_1)
  let zin_re = real(zin)
  let zin_im = imag(zin)

  let zout    = 50*(1+s_2_2)/(1-s_2_2)
  let zout_re = real(zout)
  let zout_im = imag(zout)

  let fs11c = s11db[200]
  let fs21c = s21db[200]
  let fs12c = s12db[200]
  let fs22c = s22db[200]

  let fs11worst = maximum(s11db)
  let fs11best  = minimum(s11db)

  let fs21min = minimum(s21db)
  let fs21max = maximum(s21db)

  let fnfc    = nfdb[200]
  let fnfmax  = maximum(nfdb)
  let fnfminc = nfmindb[200]

  let fzinre = zin_re[200]
  let fzinim = zin_im[200]

  let fzoutre = zout_re[200]
  let fzoutim = zout_im[200]

  let fgammac  = mag(s_1_1[200])
  let freflpct = 100*fgammac*fgammac
  let fvswr    = (1+fgammac)/(1-fgammac)

  let nf_penalty = fnfc-fnfminc
  let gain_ripple = fs21max-fs21min

  * ---------------------------------------------------------------------------
  * FINAL SUMMARY FILE
  * ---------------------------------------------------------------------------

  echo ============================================================ > compact_full_sweep_summary.txt
  echo GF180MCU_COMPACT_LNA_FULL_SWEEP_FINAL_SUMMARY >> compact_full_sweep_summary.txt
  echo REQUESTED_SOLVER KLU >> compact_full_sweep_summary.txt
  echo REQUESTED_THREADS 6 >> compact_full_sweep_summary.txt
  echo TOTAL_SEARCH_CANDIDATES 19683 >> compact_full_sweep_summary.txt
  echo SELECTION_OBJECTIVE MINIMUM_WORST_CASE_S11_DB >> compact_full_sweep_summary.txt
  echo TARGET_BAND_HZ 2.300E9 2.500E9 >> compact_full_sweep_summary.txt
  echo ============================================================ >> compact_full_sweep_summary.txt

  echo FIXED_DEVICE_PARAMETERS >> compact_full_sweep_summary.txt
  echo W_ICG_REP_M 0.25E-6 >> compact_full_sweep_summary.txt
  echo W_CG_M 40E-6 >> compact_full_sweep_summary.txt
  echo L_CG_M 0.60E-6 >> compact_full_sweep_summary.txt
  echo ============================================================ >> compact_full_sweep_summary.txt

  echo OPTIMIZED_PARAMETERS >> compact_full_sweep_summary.txt
  echo I_ICG_REP_A $best_irep >> compact_full_sweep_summary.txt
  echo M_CG $best_mcg >> compact_full_sweep_summary.txt
  echo VBIAS_CG_V $best_vcg >> compact_full_sweep_summary.txt

  echo L_IN_H $best_lin >> compact_full_sweep_summary.txt
  echo CIN_VAL_F $best_cin >> compact_full_sweep_summary.txt
  echo C_SH_IN_F $best_csh >> compact_full_sweep_summary.txt

  echo CNC_VAL_F $best_cnc >> compact_full_sweep_summary.txt
  echo R_FF_OHM $best_rff >> compact_full_sweep_summary.txt
  echo CBYP_CG_F $best_cbyp >> compact_full_sweep_summary.txt
  echo ============================================================ >> compact_full_sweep_summary.txt

  echo FINAL_DC_OPERATING_POINT >> compact_full_sweep_summary.txt
  echo VBIAS_ICG_V $final_vbi_c >> compact_full_sweep_summary.txt
  echo V_SOURCE_NODE_V $final_vs_c >> compact_full_sweep_summary.txt
  echo ID_XM2_A $final_id2_c >> compact_full_sweep_summary.txt
  echo GM_XM2_S $final_gm2_c >> compact_full_sweep_summary.txt
  echo GMBS_XM2_S $final_gmb2_c >> compact_full_sweep_summary.txt
  echo XM2_SAT_MARGIN_V $final_sat2_c >> compact_full_sweep_summary.txt
  echo XM5_SAT_MARGIN_V $final_sat5_c >> compact_full_sweep_summary.txt
  echo PDC_W $final_pdc_c >> compact_full_sweep_summary.txt
  echo ============================================================ >> compact_full_sweep_summary.txt

  echo FINAL_RF_AT_2P400_GHZ >> compact_full_sweep_summary.txt
  echo S11_DB $&fs11c >> compact_full_sweep_summary.txt
  echo S21_DB $&fs21c >> compact_full_sweep_summary.txt
  echo S12_DB $&fs12c >> compact_full_sweep_summary.txt
  echo S22_DB $&fs22c >> compact_full_sweep_summary.txt
  echo NF_DB $&fnfc >> compact_full_sweep_summary.txt
  echo NFMIN_DB $&fnfminc >> compact_full_sweep_summary.txt
  echo NF_MINUS_NFMIN_DB $&nf_penalty >> compact_full_sweep_summary.txt
  echo ZIN_RE_OHM $&fzinre >> compact_full_sweep_summary.txt
  echo ZIN_IM_OHM $&fzinim >> compact_full_sweep_summary.txt
  echo ZOUT_RE_OHM $&fzoutre >> compact_full_sweep_summary.txt
  echo ZOUT_IM_OHM $&fzoutim >> compact_full_sweep_summary.txt
  echo GAMMA_MAG $&fgammac >> compact_full_sweep_summary.txt
  echo REFLECTED_POWER_PERCENT $&freflpct >> compact_full_sweep_summary.txt
  echo VSWR $&fvswr >> compact_full_sweep_summary.txt
  echo ============================================================ >> compact_full_sweep_summary.txt

  echo FINAL_TARGET_BAND_2P3_TO_2P5_GHZ >> compact_full_sweep_summary.txt
  echo S11_WORST_DB $&fs11worst >> compact_full_sweep_summary.txt
  echo S11_BEST_DB $&fs11best >> compact_full_sweep_summary.txt
  echo S21_MIN_DB $&fs21min >> compact_full_sweep_summary.txt
  echo S21_MAX_DB $&fs21max >> compact_full_sweep_summary.txt
  echo S21_GAIN_RIPPLE_DB $&gain_ripple >> compact_full_sweep_summary.txt
  echo NF_MAX_DB $&fnfmax >> compact_full_sweep_summary.txt
  echo ============================================================ >> compact_full_sweep_summary.txt

  echo CONSTRAINT_CHECK >> compact_full_sweep_summary.txt

  if fs21min >= 19.0
    echo S21_MIN_CONSTRAINT PASS >> compact_full_sweep_summary.txt
  else
    echo S21_MIN_CONSTRAINT FAIL >> compact_full_sweep_summary.txt
  end

  if fnfmax <= 4.5
    echo NF_MAX_CONSTRAINT PASS >> compact_full_sweep_summary.txt
  else
    echo NF_MAX_CONSTRAINT FAIL >> compact_full_sweep_summary.txt
  end

  if $final_pdc_c <= 0.150
    echo PDC_CONSTRAINT PASS >> compact_full_sweep_summary.txt
  else
    echo PDC_CONSTRAINT FAIL >> compact_full_sweep_summary.txt
  end

  if $final_sat2_c >= 0.100
    echo XM2_SATURATION_CONSTRAINT PASS >> compact_full_sweep_summary.txt
  else
    echo XM2_SATURATION_CONSTRAINT FAIL >> compact_full_sweep_summary.txt
  end

  if $final_sat5_c >= 0.100
    echo XM5_SATURATION_CONSTRAINT PASS >> compact_full_sweep_summary.txt
  else
    echo XM5_SATURATION_CONSTRAINT FAIL >> compact_full_sweep_summary.txt
  end

  echo ============================================================ >> compact_full_sweep_summary.txt
  echo DETAILED_RESULTS_FILE compact_full_sweep_detailed.txt >> compact_full_sweep_summary.txt
  echo SUMMARY_FILE compact_full_sweep_summary.txt >> compact_full_sweep_summary.txt
  echo ============================================================ >> compact_full_sweep_summary.txt

  * Also append the final verified result to the detailed file.

  echo FINAL_VERIFIED_RESULT >> compact_full_sweep_detailed.txt
  echo I_ICG_REP $best_irep >> compact_full_sweep_detailed.txt
  echo M_CG $best_mcg >> compact_full_sweep_detailed.txt
  echo VBIAS_CG $best_vcg >> compact_full_sweep_detailed.txt
  echo L_IN $best_lin >> compact_full_sweep_detailed.txt
  echo CIN_VAL $best_cin >> compact_full_sweep_detailed.txt
  echo C_SH_IN $best_csh >> compact_full_sweep_detailed.txt
  echo CNC_VAL $best_cnc >> compact_full_sweep_detailed.txt
  echo R_FF $best_rff >> compact_full_sweep_detailed.txt
  echo CBYP_CG $best_cbyp >> compact_full_sweep_detailed.txt
  echo FINAL_S11_CENTER_DB $&fs11c >> compact_full_sweep_detailed.txt
  echo FINAL_S11_WORST_DB $&fs11worst >> compact_full_sweep_detailed.txt
  echo FINAL_S21_MIN_DB $&fs21min >> compact_full_sweep_detailed.txt
  echo FINAL_NF_MAX_DB $&fnfmax >> compact_full_sweep_detailed.txt
  echo ============================================================ >> compact_full_sweep_detailed.txt

  destroy $curplot

else

  * ---------------------------------------------------------------------------
  * No valid candidate.
  * ---------------------------------------------------------------------------

  echo ============================================================ > compact_full_sweep_summary.txt
  echo GF180MCU_COMPACT_LNA_FULL_SWEEP_FINAL_SUMMARY >> compact_full_sweep_summary.txt
  echo STATUS NO_VALID_CANDIDATE_FOUND >> compact_full_sweep_summary.txt
  echo TOTAL_SEARCH_CANDIDATES 19683 >> compact_full_sweep_summary.txt
  echo REQUIRED_S21_MIN_DB 19.0 >> compact_full_sweep_summary.txt
  echo REQUIRED_NF_MAX_DB 4.5 >> compact_full_sweep_summary.txt
  echo REQUIRED_PDC_MAX_W 0.150 >> compact_full_sweep_summary.txt
  echo REQUIRED_XM2_SAT_MARGIN_V 0.100 >> compact_full_sweep_summary.txt
  echo REQUIRED_XM5_SAT_MARGIN_V 0.100 >> compact_full_sweep_summary.txt
  echo DETAILED_RESULTS_FILE compact_full_sweep_detailed.txt >> compact_full_sweep_summary.txt
  echo ============================================================ >> compact_full_sweep_summary.txt

end

.endc

"


spice_ignore=true}
C {res.sym} 1020 -760 1 0 {name=R_FF
value=\{R_FF\}
footprint=1206
device=resistor
m=1}
C {capa.sym} 760 -370 0 0 {name=CBOOT
m=1
value=\{CBOOT_VAL\}
footprint=1206
device="ceramic capacitor"
spice_ignore=true}
C {lab_pin.sym} 760 -458.75 0 0 {name=p3 sig_type=std_logic lab=vm2}
C {lab_pin.sym} 760 -280 2 0 {name=p31 sig_type=std_logic lab=rf_in_pad}
C {gnd.sym} 2040 -820 0 1 {name=l4 lab=GND}
C {lab_pin.sym} 2020 -880 2 1 {name=p75 sig_type=std_logic lab=GND}
C {lab_pin.sym} 2300 -880 2 0 {name=p76 sig_type=std_logic lab=vbias_icg}
C {symbols/nfet_03v3.sym} 2060 -880 0 1 {name=M8
L=0.5u
W=\{W_ICG_REP\}
nf=1
m="1"
ad="'int((nf+1)/2) * W/nf * 0.18u'"
pd="'2*int((nf+1)/2) * (W/nf + 0.18u)'"
as="'int((nf+2)/2) * W/nf * 0.18u'"
ps="'2*int((nf+2)/2) * (W/nf + 0.18u)'"
nrd="'0.18u / W'" nrs="'0.18u / W'"
sa=0 sb=0 sd=0
model=nfet_03v3
spiceprefix=X
}
C {isource.sym} 2040 -1010 0 0 {name=I0 value=\{I_ICG_REP\}}
C {lab_pin.sym} 2040 -1080 0 0 {name=p70 sig_type=std_logic lab=vdcbias
}
C {gnd.sym} 2550 -800 0 1 {name=l5 lab=GND
}
C {lab_pin.sym} 2530 -860 2 1 {name=p77 sig_type=std_logic lab=GND
}
C {lab_pin.sym} 2840 -860 2 0 {name=p78 sig_type=std_logic lab=vbias_buf
}
C {symbols/nfet_03v3.sym} 2570 -860 0 1 {name=M10
L=0.5u
W=\{W_BUF_REP\}
nf=1
m="1"
ad="'int((nf+1)/2) * W/nf * 0.18u'"
pd="'2*int((nf+1)/2) * (W/nf + 0.18u)'"
as="'int((nf+2)/2) * W/nf * 0.18u'"
ps="'2*int((nf+2)/2) * (W/nf + 0.18u)'"
nrd="'0.18u / W'" nrs="'0.18u / W'"
sa=0 sb=0 sd=0
model=nfet_03v3
spiceprefix=X
}
C {isource.sym} 2550 -990 0 0 {name=I1 value=\{I_BUF_REP\}
}
C {lab_pin.sym} 2550 -1060 0 0 {name=p79 sig_type=std_logic lab=vdcbias
}
C {res.sym} 2200 -880 1 0 {name=RBCG1
value=5k
footprint=1206
device=resistor
m=1}
C {capa.sym} 2250 -810 0 0 {name=C1
m=1
value=10p
footprint=1206
device="ceramic capacitor"}
C {lab_pin.sym} 2250 -750 3 0 {name=p80 sig_type=std_logic lab=GND}
C {res.sym} 2740 -860 1 0 {name=RBCG2
value=5k
footprint=1206
device=resistor
m=1}
C {capa.sym} 2790 -790 0 0 {name=C2
m=1
value=10p
footprint=1206
device="ceramic capacitor"}
C {lab_pin.sym} 2790 -730 3 0 {name=p81 sig_type=std_logic lab=GND}
C {gnd.sym} 3100 -820 0 1 {name=l6 lab=GND
}
C {lab_pin.sym} 3080 -880 2 1 {name=p82 sig_type=std_logic lab=GND
}
C {lab_pin.sym} 3390 -880 2 0 {name=p83 sig_type=std_logic lab=vbias_cs
}
C {symbols/nfet_03v3.sym} 3120 -880 0 1 {name=M11
L=0.28u
W=\{W_CS_REP\}
nf=1
m="1"
ad="'int((nf+1)/2) * W/nf * 0.18u'"
pd="'2*int((nf+1)/2) * (W/nf + 0.18u)'"
as="'int((nf+2)/2) * W/nf * 0.18u'"
ps="'2*int((nf+2)/2) * (W/nf + 0.18u)'"
nrd="'0.18u / W'" nrs="'0.18u / W'"
sa=0 sb=0 sd=0
model=nfet_03v3
spiceprefix=X
}
C {isource.sym} 3100 -1010 0 0 {name=I2 value=\{I_CS_REP\}
}
C {lab_pin.sym} 3100 -1080 0 0 {name=p84 sig_type=std_logic lab=vdcbias
}
C {capa.sym} 3340 -810 0 0 {name=C3
m=1
value=4.7p
footprint=1206
device="ceramic capacitor"}
C {lab_pin.sym} 3340 -750 3 0 {name=p85 sig_type=std_logic lab=GND}
C {gnd.sym} 2560 -1220 0 1 {name=l8 lab=GND
}
C {lab_pin.sym} 2540 -1280 2 1 {name=p90 sig_type=std_logic lab=GND
}
C {lab_pin.sym} 2850 -1280 2 0 {name=p91 sig_type=std_logic lab=vbias_csc
}
C {symbols/nfet_03v3.sym} 2580 -1280 0 1 {name=M13
L=0.28u
W=\{W_CSC_REP\}
nf=1
m="1"
ad="'int((nf+1)/2) * W/nf * 0.18u'"
pd="'2*int((nf+1)/2) * (W/nf + 0.18u)'"
as="'int((nf+2)/2) * W/nf * 0.18u'"
ps="'2*int((nf+2)/2) * (W/nf + 0.18u)'"
nrd="'0.18u / W'" nrs="'0.18u / W'"
sa=0 sb=0 sd=0
model=nfet_03v3
spiceprefix=X
}
C {isource.sym} 2560 -1410 0 0 {name=I4 value=\{I_CSC_REP\}
}
C {lab_pin.sym} 2560 -1480 0 0 {name=p92 sig_type=std_logic lab=vdcbias
}
C {capa.sym} 2800 -1210 0 0 {name=C5
m=1
value=4.7p
footprint=1206
device="ceramic capacitor"}
C {lab_pin.sym} 2800 -1150 3 0 {name=p93 sig_type=std_logic lab=GND}
